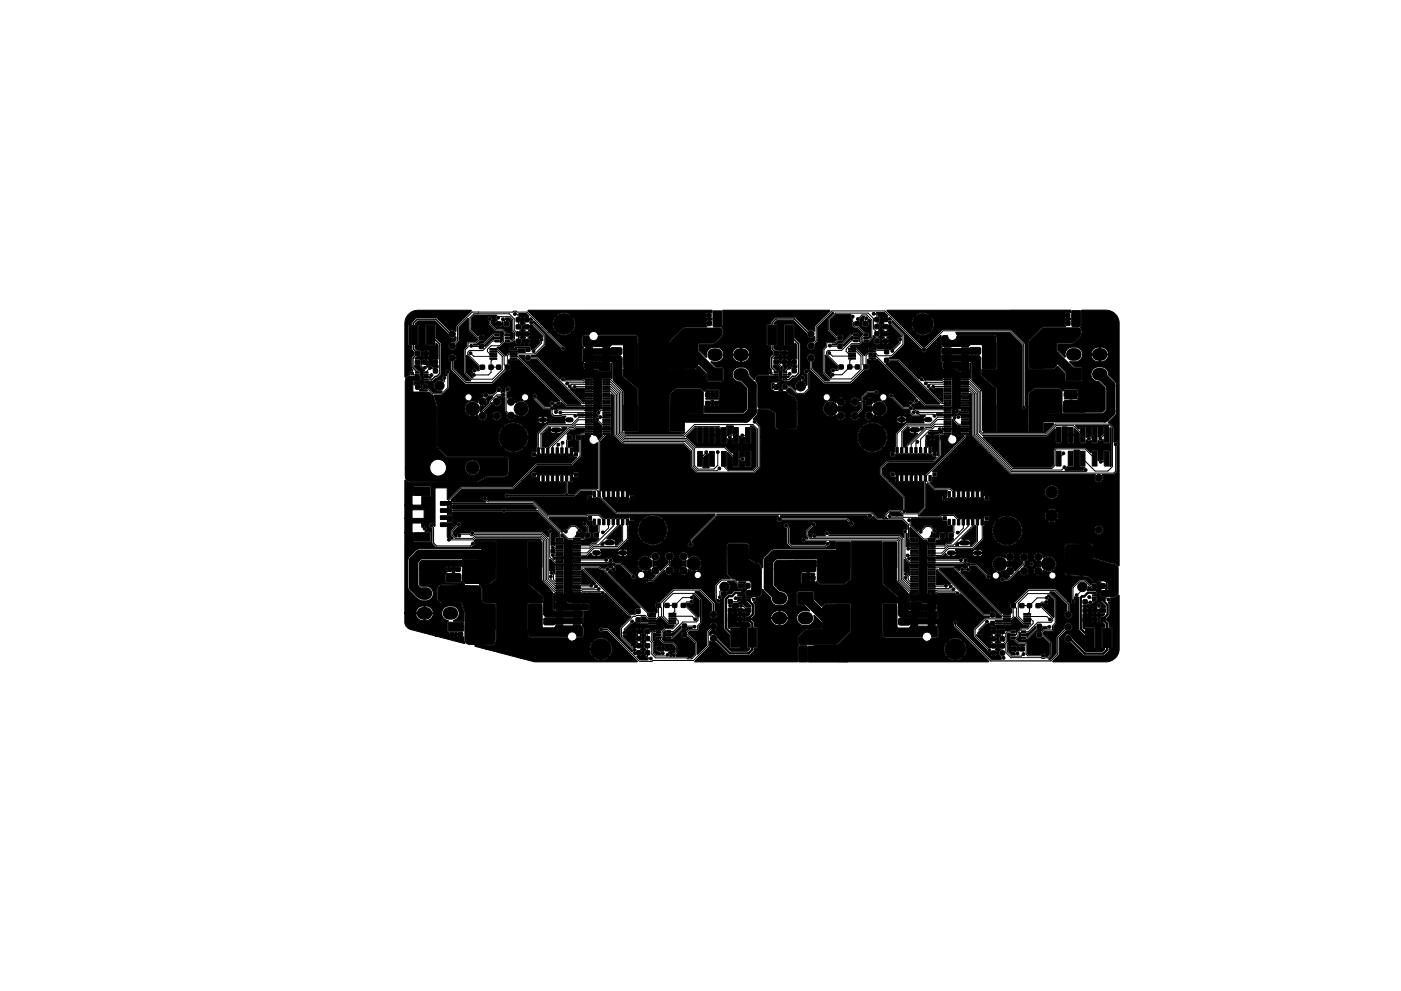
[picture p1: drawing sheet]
<svg xmlns="http://www.w3.org/2000/svg" width="297mm" height="210mm" viewBox="0 0 297 210" stroke-linecap="round" stroke-linejoin="round" font-family="sans-serif">
<g fill="#000" stroke="#000" stroke-width=".21">
<path d="M86.2 80.1l.7-.3 2 .1a.48 .48 0 0 1 .2 .5 .48 .48 0 0 1-.5 .4h-1.1v2.4h3.5l.8 .7 .7 2.1v8.9l2.2 2.1 12.6 .1 .4 .4v2.5a1 1 0 0 1-1 1h-3.5l-2.3 1.2-14-.1a1 1 0 0 1-1-1v-1.8h5.2a1.78 1.78 0 0 0 1.8 1.7 1.78 1.78 0 0 0 1.8-1.8h3.9a1.61 1.61 0 0 0 2.3 1.5 1.61 1.61 0 0 0 .2-2.8 1.61 1.61 0 0 0-2.5 1.1v.2h-3.9a1.78 1.78 0 0 0-1.9-1.8 1.78 1.78 0 0 0-1.7 1.9h-5.2v-18.5zM88.1 76.4h.9v.9h-.9zM88.1 74.6h.9v.8h-.9zM88.1 79.9h.8v.3h-.8zM88.1 79.4h.8v.3h-.8zM88.1 78.9h.8v.3h-.8zM86.7 69h1.9v4.1h-1.9zM89.8 76.4h.9v.9h-.9zM89.8 74.6h1v.8h-1zM90 78.9h.8v.3h-.8zM90 79.4h.8v.3h-.8zM90 79.9h.8v.3h-.8z"/>
<path d="M91.9 78.3h.8v.8h-.8zM91.9 76.4h.8v.9h-.8zM90.4 69h1.8v4.1h-1.8zM98.9 75.4h.2l2.5 2.5-.1 .5h-.5a.5 .5 0 0 0-.9 0v.2l.1 .4-.2 .5 .3 .6-.2 .1-1.2-1.2zM88.6 68.1h3.6l2.8 2.8 .3 .6 .7 .3 .7-.3v.7l-.5 .4a.88 .88 0 0 0-1.1 .8 .88 .88 0 0 0 1.1 .9 .88 .88 0 0 0 .5-1.3l.6-.6v-3l2-1.9 .1 2.6 1.9 1.9-.4 .5-1.8 .1-.1 .9-.6 .7v5.1l1.4 1.5h-.9l-2.6-2.6-.1-1.4a.88 .88 0 0 0 .3-1.4 .88 .88 0 0 0-1.4 .1 .88 .88 0 0 0 .5 1.3v1.7l3 3h5.7l3-2.9h.6l.3-.3v-.7l-.4-.5v-.7h1l.1-.4 .1 .4h.7l.2-.2 8.8 8.8-.7 .3h-.5a.51 .51 0 0 0-.9 0 .54 .54 0 0 0 .3 .7l-.3 .3h-1l-1.8-1.9a.51 .51 0 0 0 0-.6 .51 .51 0 0 0-.5-.3l-.3 .2-.1 .3 .3 .7 2.1 2.2h1.4l.1 .9 .5 .6h1.8l.8-.1 .1 .1-.4 .6 1.2 .1-1.2 .1 .3 .5-.1 .1h-3.8l.2-.6h-1v.6l.7-.1v.2l-2 2v2.8l-.2 .3v.8l-1 .1v.9l.9 .1 .2-.5 .8-.1 .3 .1 .8-.1 .2 .1 .8-.1 .2 .1 .8-.1 .2 .1 .8-.1 .2 .1 .8-.1 .7 .1 .3-.1 .8 .1 .1 .5 .6 .1v.1l-1.2 1.2h-7.4l-5 5h-10.8l-2.9 2.7-.1-.1v-2.4h-2.6v8.1l-.1 .1a.73 .73 0 0 0-.9-.7l-.3 .5 .2 .3 .5 .3v3.2l.8 .8 7.4 .1 .5-.4a.5 .5 0 0 0 .4-.3 .5 .5 0 0 0-.1-.6l-.1-.1 .5-.5h13.4l.3 .3-.1 .1h-2.6l-.2 .2v8.9l3.3 2.9-.1 1.2h-3l-.2 .2v6.5l.4 .6 .4 .1h7.7l.4 .5 .5 .2h4.6l1.6 1.6 1.6-1.6a2.38 2.38 0 0 0-3.2 0h-4.2l.4-.3 .3-.4h1l.4-.4 .1-1.6-.4-.7 .3-.4 .1-2.4 .7-.2 .4-.3 .1-.7-.1-.4-.6-.3h-3.8l-.5-.5h1.4v.4h3.4v-1.8h-1.5l.3-.2h3.6l.5 .5h.3l.5-.4 4.6 4.7 .7 .1-2.3 2.4v2.1l2.5 2.6 .1 .4-5.1-4.9-1.2-.1a.5 .5 0 0 0-.8 .1v.1a.51 .51 0 0 0 .5 .7l.4-.2h.8l6.4 6.5h-21.7l-3.6-.9h16a2.37 2.37 0 0 0 3.2 0l-1.6-1.6-1.6 1.6h-16l-6.7-1.8h21.9l.2 .9 .4 .8 1.6-1.7h.3l1.7 1.7a2.38 2.38 0 0 0 0-3.3l-1.7 1.6h-.3l-1.6-1.6-.4 .7-.2 .9h-21.9l-2.4-.6 .1-.2 3.5 .1 .5-.3 .4-.7v-7.9l-.2-.2h-2.2l-.5-.6-.1-2.4-.6-.8 2.2-.1 1.4-1.1v-7.8l-.1-.3h-3.1l-.2 1.6h-12.8l-.8 .4-1.4 1.3-.3 .6 .1 6.3 1.6 1.8 1.1 .6 1.1 .1 .6-.2 .6-.5 .3-.8a1.54 1.54 0 0 0-1.5-1.6h-1.1l-.4-.4v-3.3h8.1v-.6l-.5 .1-.2 .5h-.4v-.4l-.4-.2h-.2v.6h-.2v-.6l-.4 .1-.1 .5h-5.7v-1.2l.6-.6h8.3v1.3l-.6-.1v.7l-.9 .1 .1 .5h-.5v-.5h-1.3l.2 .6-.4 .5v1.2l.2 .4 .3 .2 2.6-.1 .4-.3 .6 .6h-4.9l-.8 .5-.2 .7v1.9l.6 .7 .6 .2 4 .1 .6 2v1.7h-2.2v-.2l.5-.2 .5-.6a1.55 1.55 0 0 0 0-1.4l-.4-.4-.6-.4h-1.5l-.4 .3-.5 .6-.1 .5v.7a1.54 1.54 0 0 0 1.3 1l.1 .1-.3 .4v1.6l.4 .4v.3h1.4l.1-.4 .2 .1v.3h.8v.7h.7l.2 1.3-6.3-1.6h2.9l.3 .4h.7l.3-.1 .1-.3h.3l.2 .3h.4v-.5h-.6v.2l-.9-.2v.6h-.2v-.6h-.6v.2h-2.9l-5.3-1.4a1.78 1.78 0 0 1-1.2-1.4v-1.9h2.4v.2a1.55 1.55 0 0 0 1.4 1.3h.3a1.58 1.58 0 0 0 1.9-1.5h-1.7v1.5h-.2v-1.5h-4.1v-.2h6.1a1.54 1.54 0 0 0-1.5-1.4h-.3v1.4h-.2v-1.4a1.54 1.54 0 0 0-1.7 1.4h-2.4v-17h1.8l.1 1.8 .1 .2h3.5l.1-.2v-1.9l-1.3-.2a.56 .56 0 0 0 .4-.5 .56 .56 0 0 0-.5-.6l-.6 .2v-.8h-2v2h-1.6v-3h4.1v-1.8h-2.5v1.8h-1.6v-2.8h3.6v-1.8l1.8-.1 .2-.1v-2l-.2-.1-3.5 .1v1.8l-.3 .1v2.1h-1.6l.1-5.3 1 .4 14 .1 .5-.2 1.9-1h3.8l.6-.5 .2-.6v-2.6l-.1-.4-.4-.2-12.6-.1-1.8-1.7h13.7a3.2 3.2 0 0 0 4.3 0l-2.2-2.2-2.1 2.2h-13.7l-.3-.3v-2.1h12.9l.2 1.1 .7 1.2 2.2-2.2h.3l2.2 2.2a3.1 3.1 0 0 0 0-4.4l-2.2 2.2h-.3l-2.2-2.2a3.1 3.1 0 0 0-.9 2.1h-12.9v-2.2h14l2.1 2.1 2.2-2.1a3.2 3.2 0 0 0-4.3 0h-14v-3.8h5.8a1.72 1.72 0 0 0 1 1.5 1.72 1.72 0 0 0 1.8-.2l.1 .1a.96 .96 0 0 0 .9 1.1 .96 .96 0 0 0 1-.9h1.1a.96 .96 0 0 0 .9 .9 .96 .96 0 0 0 1-1l-.3-.7-.7-.2-.6 .2-.3 .7h-1.1l-.2-.5-.4-.5 1.4-1.4 .2-.4 .6 .7a.96 .96 0 0 0 1.4-.8l-.2-.6-.7-.5v-.1l.6-.1 .5 .4h.5v2.8l.5 .6a.99 .99 0 0 0 .6 1.4h5.9l.4 .5 .6 .1v-.6h-6.6l.6-.2h7.2l-.2-.4-.5-.3h-.3v.7h-.2v-.7l-.6 .1-.4 .6h-5l.2-.4 .1-.6 .2 .1a1.69 1.69 0 0 0 2.4-.6 1.69 1.69 0 0 0-.7-2.4l.2-.1a.76 .76 0 0 0 .7-.4 .76 .76 0 0 0-.2-.8l-.5-.3a.76 .76 0 0 0-.8 .6l.1 .6 .3 .3-.1 .1h-.7l-.9 .3-.2-.8-.8 .7 .6-.8a1.09 1.09 0 0 0-1.3 0v-1.3a.61 .61 0 0 0 .7-.6 .61 .61 0 0 0-.6-.6 .61 .61 0 0 0-.6 .7l-.1 .5h-.8a.62 .62 0 0 0-.2-1.1 .62 .62 0 0 0-.8 .7l-.7 .8h-1a.64 .64 0 0 0-.9-.2 .64 .64 0 0 0-.2 .8l-.7 .3 1.4 1.3a.99 .99 0 0 0-.1-1.3l.5-.4 1 .1-.8 .9v.4l-1.9 1.9v-1.3l.7 .1 .4-.2-1.3-1.4-.3 .8-.9-.3h-.7a.97 .97 0 0 0 .3-1.2l-.6-.4a.76 .76 0 0 0-.8 .5 .76 .76 0 0 0 .3 .9l.6 .3-.7 .6-.3 .9h-5.8v-.7l-.7-2.1 1.7-.1 1.4-1.4 .2-3.3a.51 .51 0 0 0-.1-.7 .51 .51 0 0 0-.7 .1 .51 .51 0 0 0 0 .7l.2 .5-.2 .1a.51 .51 0 0 0-.6 0 .51 .51 0 0 0-.1 .6l.2 .2-.2 .2a1.19 1.19 0 0 0-1.3 0l-.5 .6a1.26 1.26 0 0 0 .4 1.3 1.26 1.26 0 0 0 1.3 .3l-.2 .3h-1.7l-.9-1-.2-.8-.8-.2-.4 .4 .1 .8 .3 .2h.6l.1 .2-1.6 .1-.1-.2 .3-.2 .1-.4h-.7l-.1-.2h.8l-.2-.5-.4-.2v.7h-.2v-.7l-.8 .3 .1-.6 1.1-.1 .4-.6-.2-.6v-.9l-.4-.1-.8-.8 .1-.4h.9l1.1 1-.3 .4 .1 1h1.3l.3 .2-.1 .2-1.5-.2 .1 .8h1.7l.8-.7 .4-.1 .8-.8v-6.3l-1.2-1.3v-2.7l-.2-.2h-1.9l-.1 .2v4.2l.1 .1h1.9l.3-.5 .4 .4v2.9l-.5 .1v1.3h.5v.5h-.9l-.4-.2a.52 .52 0 0 0-.9 .1 .23 .23 0 0 1-.3-.3 .23 .23 0 0 1 .4-.1l.2-.3h.7l.2 .3h.3v-.5l-1.2 .2v-.3h-1.5v.4l-.2-.1v-.4h2.9v-.6l-.4 .1-.1 .5h-2.4l1.7-.1v-.2l-.2-.3h-.4v.5h-.2v-.5h-.3l-.3 .2-.1 .3h-.2l-.3-.5-1-.1 .4-.4 .7-.1 .2-.3h.2l.4 .4 .9-.1 .2-.3v-.2h-.6v.5h-.2v-.5h-.6l-.1 .2h-.2v-.4h1.7l-.2-.6h-.4v.6h-.2v-.6l-.4 .1-.3 .5h-.2l-.1-.5-.8-.1-.4-.4v-.5l.6-.1 .2-.2v-4.1l-.2-.2h-.6zM86.7 66.6a2.79 2.79 0 0 1 1.9-.8h11.3v.2l-3.2 3.2v1l-.1 .1a.88 .88 0 0 0-1.1-.2l-.2 .1-2.9-2.8h-4l-1 .9-.1 .5-.7 .1-.1 4.3 .7 .1 .1 .9 .5 .6v.4l-.6 .7v2.2l.3 .4-.2 .1a.5 .5 0 0 0-.4 .7v.3l-1.1 .4 .1-11.7 .2-.9zM99.9 67.5l.7-.7h4.6l.1 .2-.1 .1a.63 .63 0 0 0 .2 .9l-.4 .3v.3h1.4v-.3l.2-.1 .2 1.1 1 .1 .3-.2v-.8l-.2-.3-.5-.1-.3-.5 .9-.1 .4 .5v2.2l.4 .6v1l-.3 .4h-.2l-.1-.3-.7-.1v-.1h.7v-.9l-.7-.1-.9-.8-1.3-.1-.8-.7h.5l.3 .4h.7l.4-.2v-.4h-.6v.6h-.2v-.6h-.6v.2h-.5l-.4-.5 .1-.4a.51 .51 0 0 0 0-.8 .51 .51 0 0 0-.8 .1 .51 .51 0 0 0 .2 .7v.8l1.4 1.3 1.4 .1 .4 .4-.3 .5v1.1l-.4 .4-.1-.9h-1.3v.3l-.5 .1-1.3 1.3h-.2l.1-.3 1.8-1.8h.1v.2h1.3v-.9l-1.1-.1-.6 .3-1.9 1.9-.8 .1-.3 .3h-.8l-.1-.2h.7l.7-.6 .8-.2 .1-.8-.4-.4h-.6l-.4 .2-1.4-1.3zM101.9 77.5h.8v.8h-.8zM101.6 73.1h.9v.8h-.9zM101.6 71.3h.9v.8h-.9zM103.7 77.5h.8v.8h-.8zM105.3 77.5h.9v.8h-.9z"/>
<path d="M103.9 76h1.4v.2h-1.4zM103.9 75.5h1.4v.2h-1.4zM103.9 75h1.4v.2h-1.4zM103.9 74.5h1.4v.2h-1.4zM103.9 74h1.4v.2h-1.4zM104.9 72.1h.9v.4h-.9zM104.9 71.5h.9v.4h-.9zM104.9 70.8h.9v.4h-.9zM105.2 68.3h1v.8h-1zM107.1 77.5h.9v.8h-.9zM106.9 68.3h1v.8h-1zM107.1 70.8h.9v.4h-.9z"/>
<path d="M107.1 71.5h.9v.4h-.9zM107.1 72.1h.9v.4h-.9zM109.5 68.9h.9v.9h-.9zM109.5 72h.9v.8h-.9zM108.2 74h1.4v.2h-1.4zM108.2 74.5h1.4v.2h-1.4zM108.2 75h1.4v.2h-1.4zM108.2 75.5h1.4v.2h-1.4zM108.2 76h1.4v.2h-1.4zM109.5 70.5h.8v.8h-.8zM109.5 67.4h.8v.9h-.8zM111.2 68.9h.9v.9h-.9z"/>
<path d="M111.2 72h.9v.8h-.9zM110.1 75.4h1.2v.9l.3 .3h.8l.3-.4h1.1l9.4 9.5-3 .1-10.2-10.2zM110 66.6l1.7-.1 .5 .6-.4 .1v.5h.6l.1-.3 .4 .5-.1 .1h-1.8l.1 .3 .2 .3-.3 .3-.1 .3h1.5v-.3h.3l2.4 2.4v.2l-.7 .3-.1 .4 .2 .5-1.3 1.3-.5 .2-.1-.6-.3-.2-3.1 .1-.4 .3h-.8v.7h1.8l.1-.5h1.3l.2 .8-3.4-.1-.8 .8-1.8-1.7 .6-.2 .9-.9h1.1l.7-.1 .4-.3 .1 .5 .4 .3h.7l.4-.4h.2l.4 .4h.7l.4-.4v-.2h-.6v.6h-.2v-.6h-.7v.2h-.2v-.4h1.7l-.1-.4-.3-.3 .3-.3 .1-.3h-1.4l.1 .3 .3 .3-.4 .3-.1 .4h-.2l-.1-.5-.4-.2 .4-.5v-.6l-.4-.4 .5-.5h.2l.5 .5-.3 .3-.1 .4h1.4l-.1-.4-.3-.3 .3-.3 .1-.3-1.5-.1v.2h-.2l-.1-.7-.3-.4 .2-.2 .1-.6h1v-.5l-.5 .1-.1 .4h-.4l-.1-.3-.3-.3zM111.5 73.7h.8v.8h-.8zM111.5 75.5h.8v.8h-.8zM111.3 70.5h.8v.8h-.8zM111.3 67.4h.8v.9h-.8zM123.6 75.5l7.8-.1 .5 .5v3.9l3.2 2.8-.1 8.8-2.7-.1v-8.2l-2.3-2.5v-3.5l-.3-.3-.4-.1h-5.6l-.1-.1zM124.1 72.4h1.5v.3h-1.5zM124.1 72.9h1.5v.3h-1.5zM124.1 73.4h1.5v.3h-1.5zM124.1 73.9h1.5v.3h-1.5z"/>
<path d="M124.1 74.4h1.5v.3h-1.5zM124.1 74.9h1.5v.3h-1.5zM124.1 75.4h1.5v.3h-1.5zM124.1 75.9h1.5v.3h-1.5zM124.1 76.4h1.5v.3h-1.5zM124.1 76.9h1.5v.3h-1.5zM124.1 77.4h1.5v.3h-1.5zM124.1 77.9h1.5v.3h-1.5zM124.1 78.4h1.5v.3h-1.5zM124.1 78.9h1.5v.3h-1.5zM124.1 79.4h1.5v.3h-1.5zM124.1 79.9h1.5v.3h-1.5z"/>
<path d="M123.7 71.4l1.1-.2a1.12 1.12 0 0 0 1.6 .9l.6-.9 7.9 .1 .2 .5-.1 6.2-.4 .2h-1.8l-.5-.2-.1-4.9h-2.5l-.7 .4h-5l-.4-.4v-1.4zM122.4 78.5h3.4v.4h3.5v1.3l-6.9 .1zM124 77l.4-.1h4.6l.4 .4v1.1l-.3 .3h-1.9l-.2-.1v-.4h-2.9l-.2-.4zM127.8 72.4h1.5v.3h-1.5zM127.8 72.9h1.5v.3h-1.5zM127.8 73.4h1.5v.3h-1.5zM127.8 73.9h1.5v.3h-1.5zM127.8 74.4h1.5v.3h-1.5zM127.8 74.9h1.5v.3h-1.5zM127.8 75.4h1.5v.3h-1.5zM127.8 75.9h1.5v.3h-1.5zM127.8 76.4h1.5v.3h-1.5z"/>
<path d="M127.8 76.9h1.5v.3h-1.5zM127.8 77.4h1.5v.3h-1.5zM127.8 77.9h1.5v.3h-1.5zM127.8 78.4h1.5v.3h-1.5zM127.8 78.9h1.5v.3h-1.5zM127.8 79.4h1.5v.3h-1.5zM127.8 79.9h1.5v.3h-1.5zM129.6 77.1l.2 .1-.1 3.1-.4-.2v-.2h.2v-.2l-.2-.1 .2-.4-.2-.1v-.2h.2zM123.6 74.1l5.8-.1 .4-.3h1.8l.3 .3v1l-.3 .2h-7.9l-.1-.1zM132.3 72.8h2.9v5.4h-2.9zM142.2 72.8h2.9v5.4h-2.9zM150 69.8h.8v1h-.8z"/>
<path d="M150 68.1h.8v1h-.8zM149.9 66.5h.8v.8h-.8zM151.7 69.8h.8v1h-.8zM151.7 68.1h.8v1h-.8zM142.5 72.1l2.3-2.2 .5-.3h7.2l.4 .2 .2 .4-.1 .9-1.5 1.6-.5 .1h-3v4.4a1 1 0 0 1-1 1h-3.8a1 1 0 0 1-1-1v-4.4zM151.7 66.5h.9v.8h-.9zM151.2 66h1.9v3l-.2 .4-1.6-.1-.1-.3zM160.4 80l.6-.3 3.9 .1 .2 .4-.2 .7-1.4 .2v1.5l.8 .5 2.6 .1a1.56 1.56 0 0 0 1.3 1l.7 1.1v5.4l-.5 .2-3.7-.1-.2-.4v-2.8l-1.4-.9h-1.9l-.5-.3v-4.6l-.5-1 .1-.5zM164.1 76.4h1v.8h-1zM164.1 74.5h1v.8h-1zM164.1 79.9l.8-.1v.3h-.8zM164.1 79.4l.8-.1v.3h-.8z"/>
<path d="M164.1 78.9l.8-.1v.3h-.8zM162.8 69h1.8v4.1h-1.8zM165.9 76.4h.9v.8h-.9zM165.9 74.5h.9v.8h-.9zM166 78.9l.8-.1v.3h-.8zM166 79.4l.8-.1v.3h-.8zM166 79.9l.8-.1v.3h-.8zM168 78.2h.8v.9h-.8zM168 76.4h.8v.8h-.8zM166.4 69h1.9v4.1h-1.9zM175 75.4h.1l2.5 2.5-.1 .4h-.5a.5 .5 0 0 0-.8 0v.8a.5 .5 0 0 0 0 .8l.1 .2h-.2l-1.1-1.1zM112 65.8h38.9v.5h-.5v1.3l.5-.1 .1 .3-.5 .1-.1 .8h-.7l.1 .7-4.8 .1-2.8 2.6-.2 .7v5.5l.1 .1h4.9l.7-.2 .5-.5 1.5 1.6 .1 1.3 .2 .4h3.1l.4-.4-.1-2.5-.3-.2h-1.4l-1-1.1h1.5l.4-.2 .6-.5 .3-.7h1.8a1.56 1.56 0 0 0 1.7 1.4h.2a1.52 1.52 0 0 0 1.8-1.5l-1.8 .1v1.4h-.2v-1.5l-3.5 .1v-.3h5.4a1.51 1.51 0 0 0-1.4-1.4h-.3v1.4h-.2v-1.4a1.56 1.56 0 0 0-1.7 1.4h-1.8l-.1-.2a1.57 1.57 0 0 0-1.4-1.2l-1.2 .1-.6 .4-.4 .6-.1 1-1.5-1.4 .1-1.4h3.1l1.7-1.6 .2-.7v-.7l-.3-.4 .3-.6v-3.2h22.6v.2l-3.1 3.1v1.1l-.2 .1a.88 .88 0 0 0-1.1-.2h-.1l-2.8-2.7h-4.3l-.9 .9-.1 .4-.6 .1-.1 .2v4.2l.7 .1 .1 .8 .5 .6v.5l-.6 .7v2.1l.3 .5-.6 .3-.1 .7-2.1 .1-.6 .4-.2 .5-1-.9-.1-.7a1.55 1.55 0 0 0-1.3-1l-1.3 .1-.6 .4-.4 .8 .1 .8a1.55 1.55 0 0 0 1.3 1h.3l1.3 1.3v4.6l-.7 .6h-8.2v-1.4l1.1 .1 .3-.3h.4l.3 .3 .7 .1 .3-.3 .1-.3h-.6v.5h-.2v-.5h-.5l-.1 .2h-.4v-.2h-.6v.5h-.2v-.7h.8v-.6h.5l-.1 .6h1.4l-.2-.6 .2-.3v-1.7l-.1-.2-2.8-.1-.4 .4-.9-.7h-5l-1.5 1.3v7.7l.2 .3h3l.1 .2-.3 .3h-12.1l-.3-.5h2.7l.2-.2-.1-8.9-3.2-2.8 .1-1.3h3l.1-.1v-6.7l-.3-.4-.4-.2-7.7 .1-.4-.5a.99 .99 0 0 0-1.6 .4l-1.1 .1-.4 .5v1.6l.3 .5-.3 .4v1.4v1.2l.4 .3-.1 .9 .2 .5 2.8 .1 .5 .4h-1.4v-.4h-3.4v1.8h1.4l-.2 .2h-3.8a.51 .51 0 0 0-.4-.5 .51 .51 0 0 0-.5 .4h-.2l-4.7-4.7-1.4-.1 .1-.2 .9-.1 2.1-2.2-.1-2.1-2.5-2.5v-.4l5.8 5.7 .2 .5a.5 .5 0 0 0 .8-.2 .53 .53 0 0 0-.6-.7l-2.9-2.9h1.5a2.37 2.37 0 0 0 3.3 0l-1.7-1.6-1.6 1.6h-1.5l-1.7-1.8h2.4l.2 .9 .5 .8 1.6-1.7h.3l1.6 1.7 .5-.8 .1-1.1h28.4v-.7l-.5 .2-.1 .5h-27.8l-.5-1.3h28.2l.2 .4h.4v-.5l-.6-.1v.2h-28.2l-.1-.1-1.6 1.6h-.3l-1.6-1.6-.5 .7-.2 .9h-2.4l-1.8-1.7h5l1.6 1.6 1.7-1.6-.2-.2h29.2v-.5l-.4 .1-.2 .4h-28.6l-.2-.1a2.38 2.38 0 0 0-2.9 .3h-5l-.9-1z"/>
<path d="M117.3 86l.2-.2 .6 .2a.5 .5 0 0 0 .8-.2l.1-.5 1.1 1 5.7 .1v-6.1h1.8v6.1h1.9v-2.8l.6 .5 .1 8.4 1.8 1.8h12.9l1.5 1.5v3.4l1.3 1.3 12.3-.1 1.2-1.2v-4.1h21.6a3.2 3.2 0 0 0 4.3 0l-2.2-2.2-2.1 2.2h-21.6v-2.4h20.5a3.1 3.1 0 0 0 .9 2.3l2.2-2.2h.3l2.2 2.2a3.2 3.2 0 0 0 0-4.4l-2.2 2.2h-.3l-2.2-2.2a3 3 0 0 0-.9 2.1h-20.5v-2.4l-.7-.8a.58 .58 0 0 0-.8-.5l.9-1.1 .1-1.1 2.3 .1 1.3 .9v2.7l.2 .4 .3 .2h3.8l.4-.2 .1-.4h13.7l2.1 2.1 2.2-2.1a3.2 3.2 0 0 0-4.3 0h-13.7v-3.8h5.4a1.72 1.72 0 0 0 1 1.5 1.72 1.72 0 0 0 1.8-.2v.1a.96 .96 0 0 0 .9 1.1 .96 .96 0 0 0 1-1h1.1a.97 .97 0 0 0 1 1 .97 .97 0 0 0 .9-1l1.1 .1a.97 .97 0 0 0 1 .9l5.8-.1 .3 .6 .7 .1v-.7h-6.5l.4-.2h7.3l-.2-.4-.5-.2h-.3v.6h-.2v-.6h-.3l-.5 .2-.2 .4h-5.1l.4-.9a1.67 1.67 0 0 0 2.4-.4 1.67 1.67 0 0 0-.7-2.4l.1-.2a.77 .77 0 0 0 .8-.7l-.2-.5-.6-.3a.76 .76 0 0 0-.6 .5 .76 .76 0 0 0 .1 .8l.2 .3h-1l-.6 .4-.3-.9-1.3 1.4a.98 .98 0 0 0 1.1 .1v1.3l-.5-.1-.5 .1-.3 .3-.2 .5h-1.1v-.5l.7-.8v-1.7h.4l.2 .6 .6-.6-.6-.6-.2 .6h-.4l.1-.7h.7l.6 .6 .6-.6a.9 .9 0 0 0-1.2 0h-.7l1-1h1.4l.1 .1a.52 .52 0 0 0 .8-.1 .52 .52 0 0 0-.2-.8 .52 .52 0 0 0-.7 .3h-1.7l-1.3 1.3v.8l-.4-.6-.5-.2h-.6l-.4 .4a.97 .97 0 0 0 .4 1.4 .97 .97 0 0 0 1.4-.7l.1 .1v1.2l-.7 .7-.4-.1-.5 .1-.3 .3-.2 .5h-1.1l-.1-.5-.3-.3-.5-.1-.6 .1v-1.3l.7 .1 .5-.2-.8-.8h.3l.6 .6a.95 .95 0 0 0 .1-1.1l-.7 .5h-.3l-.6-.6-.2 .8-.7-.3-1-.1 .4-.5h1.7l.6 .6 .6-.6a.9 .9 0 0 0-1.2 0h-1.7l-.1-.6-.5-.4a.76 .76 0 0 0-.8 .5 .76 .76 0 0 0 .2 .9l.7 .3-.7 .6-.3 .9h-5.4v-1.6l-.4-.8-.4-.3a1.3 1.3 0 0 1-1.2-.8l-.4-.4 .4-.4 .3-.1 1.4 1.4 1.8-.1 1.1-1.1-.1-3.5a.77 .77 0 0 0-.7-.7 .5 .5 0 0 0-.5 .5 .5 .5 0 0 0 .4 .5l.3 .1v2.4l-.7-.9v-.4l.3-.4a.5 .5 0 0 0-.7-.5 .5 .5 0 0 0-.2 .8v.3l-.7 .3-.4 .5-.1 .4 .1 .9-.9-.9-.7-.1-.4-.4h-.6l-.3 .2-.1 .8 .2 .5h-.7v-.7h-1.3v.3l-.2-.1 .1-1.1h.3l-.2 .7h1.3v-.4l-.4-.3 .4-.3 .1-.4-.2-1.8-.4-.2-.7-.7v-.5l1 .1 .3 .2v.6l.6 .3-.1 1.3 1.6-.1-.3 .4-1.3-.1 .1 .7 1.5 .1 .7-.7 .8-.1 .8-.9v-6.2l-1.2-1.4v-2.7l-.2-.1h-1.9l-.2 .2v4.2l.2 .1h1.9l.3-.5 .4 .4v2.9h-.5v1.4h.4l.1 .4-.9 .1-.2-.2a.58 .58 0 0 0-1-.1l-.1 .5-.4 .4h-.3l.1-.5-.2-.6 .8-.1 .3-.3h.6l.2 .4h.4v-.6l-1.2 .2v-.2h-.7v.6h-.2v-.6h-.6l-.1 .2-.2-.4h3v-.6l-.5 .2-.1 .4h-2.4h1.7l.1-.2-.3-.3-.4-.1v.6h-.2v-.6h-.3l-.3 .3v.3h-.3l-.2-.5-1.1-.1 .5-.5h.6l.3-.4h.2l.4 .4h.8l.3-.4v-.2h-.7v.6h-.2v-.6h-.6v.2h-.2v-.4h1.7l-.3-.5h-.4v.5h-.2v-.5h-.4l-.2 .5h-.2l-.2-.4-.8-.2-.4-.4 .1-.5h.6l.1-.2v-4.1l-.1-.2h-.6v-.2l.6-.6h3.6l2.8 2.8v.2a.87 .87 0 0 0 .7 .7 .87 .87 0 0 0 .8-.3l.2 .7-.5 .5a.88 .88 0 0 0-1.2 .8 .88 .88 0 0 0 1.1 .9 .88 .88 0 0 0 .6-1.3l.6-.7v-2.9l3.1-3.1h.2v.1l-1.3 1.4v2.1l2 2.1-.5 .4-1.8 .1-.1 1-.6 .7v5l1.4 1.6h-.9l-2.6-2.7v-1.4a.88 .88 0 0 0 .2-1.4 .88 .88 0 0 0-1.3 .2 .88 .88 0 0 0 .4 1.3l.1 1.7 3 2.9h5.7l3-2.8 .5-.1 .4-.2v-.8l-.4-.4v-.8l1 .1 .1-.4 .1 .4h.6l.3-.2 8.2 8.2-.4 .5a.23 .23 0 0 1 0 .3 .23 .23 0 0 1-.4-.1 .51 .51 0 0 0-.7 .1 .51 .51 0 0 0 .1 .7l.1 .2-.3 .2h-1l-2.2-2.3a.51 .51 0 0 0-.4-.6 .51 .51 0 0 0-.6 .5l.2 .4 .5 .2 2.3 2.3 1.3 .1 .1 .1 .1 .7 .5 .6h1.4l.3-.2h1l.1 .2-.4 .3-.1 .3 1.2 .1-1.2 .1 .2 .5-.1 .1h-3.7l.2-.6h-1v.7l.6-.1 .1 .2-2.1 2v2.8l-.2 .2v.8l-1 .2v1h1l.2-.5 .8-.2 .2 .2 .8-.2 .2 .2 .8-.2 .2 .2 .8-.2 .2 .2 .8-.2 .2 .2 .8-.2 .8 .2 .2-.2 .8 .2 .1 .5h.8l.1 .1-.7 .7h-9.6l-1.6 1.5v1.6l4.9 4.9v2.3l-.3 .3-2.7-.1-.8 .8-.1 .6-.2 .2h-1.3l-1.3-1.2-54.1-.1-2.8-2.9 .6-.1 .8 .1 .2-.1 .8 .1 .2-.1 .8 .1 .2-.1 .8 .1 .2-.1 .9 .1 .1 .6h.8l.2-.2v-.7l-.1-.2-1.3-.2v.7h-.2v-.9h.6v-.5l-.4-.2v.7h-.2v-.7l-.4 .2-.4-.2v1.6h-.2v-1.6l-.4 .2-.4-.2v1.6h-.2v-1.6l-.4 .2-.4-.2v1.6h-.2v-1.6l-.4 .2-.4-.2v1.6h-.2v-1.6l-.4 .2-.4-.2v1.6h-.2v-1.6l-.4 .2-.2-.2v-10.3l1.2-1.3 .9-.1 .1-1.1h-1.9v1l.1 .3-.8 .8-.4-.7-.7-.3v-1.2l-1.9 .1-.1 .6h-.6l-.3 .3-.8 .1-.2 .3 .1 .9 .7 .2v2.3h-1.1l-.1-1-.6-.1-.3 .1-.2-.2v-1.2l.9-.1 .1-.9-.2-.3h-.9l-.1-.2 .7-.6 .8-.1 .5-.5 3.6 .1v-2h.3l.1 .4 .5 .1 .9 .9v.6h1.9v-2.7l-1-.2 1-.1v-1.2l-1.9-.1-.8 .5a.5 .5 0 0 0-.4 .5 .5 .5 0 0 0 .4 .5l-.1 .3-.4 .1-.2 .4h-.3v-.8l-3.3 .2v-.5l3.3 .1v-1.3l-7.4 .1-.8 .3-.1-.5zM177.9 77.4h.9v.9h-.9zM177.7 73h.8v.9h-.8zM177.7 71.2h.8v.9h-.8zM179.7 77.4h.9v.9h-.9zM177.2 66.7h3.2l-.1 .5 .2 .4 .2 1.6 .4 .5h.7l1.2 1.2-.7 .7v.9l-.2-.1v-.6h-1.3l-.1 .2-.4 .1-1.4 1.3h-.1v-.3l1.8-1.8h.2v.3l1.3-.1-.1-.8-1-.1-.6 .2-2 1.9-.7 .1-.4 .4h-.9v-.2h.7l.7-.6 .7-.1 .3-.3-.1-.9-.9-.1-.4 .2-1.4-1.4v-1.8zM181.4 77.4h.8v.9h-.8zM179.9 75.9h1.5v.3h-1.5zM179.9 75.4h1.5v.3h-1.5zM179.9 74.9h1.5v.3h-1.5zM179.9 74.4h1.5v.3h-1.5zM179.9 73.9h1.5v.3h-1.5z"/>
<path d="M181 72.1h.9v.4h-.9zM181 71.5h.9v.4h-.9zM181 70.8h.9v.4h-.9zM181.3 68.3h.9v.8h-.9zM183.2 77.4h.8v.9h-.8zM182.8 67.1h.5l-.2 .9-.4 .4v.6l.3 .3h.8l.3-.1 .1-.8-.2-.4 .2-.3 .4 .3v3.5l-.3 .3-.8-.1 .8-.2-.1-.8-.7-.1-1.2-1.2 .2-.6-.9-.1 .1-.1h.8l-.2-.5 .1-.5zM183 68.3h.9v.8h-.9zM183.2 70.8h.9v.4h-.9zM183.2 71.5h.9v.4h-.9zM183.2 72.1h.9v.4h-.9zM185.5 68.9h1v.8h-1zM185.5 71.9h1v.9h-1z"/>
<path d="M184.2 73.9h1.5v.3h-1.5zM184.2 74.4h1.5v.3h-1.5zM184.2 74.9h1.5v.3h-1.5zM184.2 75.4h1.5v.3h-1.5zM184.2 75.9h1.5v.3h-1.5zM185.5 67.4h.8v.8h-.8zM185.5 70.4h.8v.8h-.8zM187.2 68.9h1v.8h-1zM187.2 71.9h1v.9h-1zM185.8 66.3h1.7l.7 .7-.3 .1v.6h.5l.1-.3 .5 .4-.1 .1h-1.8v.3l.3 .3-.4 .4v.3h1.4l.1-.3h.3l2.3 2.3v.2l-.7 .3v.4l.2 .6-1.3 1.3-.6 .2-.4-.3-2.2 .2-.4-.4h-1.6l-.1 .8h1v.1l-1 .1-.8 .7-1.7-1.7h-1.1l-.1-.2 .4-.3h1.6l.6-.6 .3 .1h1l.8-.8 .2-.7 .5 .4-.4 .4v.7l.2 .3h.9l.3-.4h.3l.3 .4h.8l.3-.3v-.2h-.6v.5h-.2v-.5h-.6v.1h-.3v-.4h1.8l-.1-.3-.4-.3 .4-.3v-.4h-1.3v.4l.4 .3-.4 .2-.1 .4h-.3l-.1-.4-.4-.2 .4-.5v-.6l-.3-.4 .4-.5h.3l.4 .5-.3 .3v.3h1.3v-.3l-.3-.3 .3-.3 .1-.4h-1.5v.2h-.3v-.7l-.4-.4 .3-.3v-.5h1.1v-.6l-.5 .1-.1 .5h-.5v-.3l-.4-.3zM187.6 74.2h.8v.8h-.8zM187.6 76h.8v.9h-.8z"/>
<path d="M187.3 67.4h.9v.8h-.9zM187.3 70.4h.9v.8h-.9zM189.1 68.1l6.3 6 .1 .4a.5 .5 0 0 0 .7 .1l.2-.5 3.1-2.9-.1 1.8 .4 .7-.3 .4v2.4l.3 .4-.1 .8 .3 .7h2.7l.5 .5h-1.4v-.4h-3.4v1.8h1.5l-.3 .2-3.7-.1a.5 .5 0 0 0-.4-.4 .5 .5 0 0 0-.6 .3l-.2 .1-4-4.1-2-.2-.1-.3 .6-.1 2.5-2.6v-2.1l-2.5-2.5zM187.8 77.2l.6-.1 .3-.4h1.7l8.8 9h-2.9zM199.6 75.4h7.9l.4 .5v3.9l3.3 2.7-.1 8.8h-2.8v-8.1l-.2-.5-2.1-2.1v-3.5l-.2-.3-.4-.1h-5.6l-.1-.2zM200.2 72.4h1.5v.3h-1.5zM200.2 72.9h1.5v.3h-1.5zM200.2 73.4h1.5v.3h-1.5zM200.2 73.9h1.5v.3h-1.5zM200.2 74.4h1.5v.3h-1.5zM200.2 74.9h1.5v.3h-1.5zM200.2 75.4h1.5v.3h-1.5z"/>
<path d="M200.2 75.9h1.5v.3h-1.5zM200.2 76.4h1.5v.3h-1.5zM200.2 76.9h1.5v.3h-1.5zM200.2 77.4h1.5v.3h-1.5zM200.2 77.9h1.5v.3h-1.5zM200.2 78.4h1.5v.3h-1.5zM200.2 78.9h1.5v.3h-1.5zM200.2 79.4h1.5v.3h-1.5zM200.2 79.9h1.5v.3h-1.5zM199.8 71.3l1-.1a1.12 1.12 0 0 0 1.7 .9l.5-.9 7.9 .1 .3 .4-.1 6.2-.4 .3h-1.9l-.4-.3-.1-4.8h-2.5l-.7 .4h-5.1l-.4-.5v-1.3zM198.4 78.5h3.4v.4h3.6v1.3l-7 .1zM200.1 77l.3-.1h4.6l.4 .3v1.1l-.3 .4h-1.8l-.2-.1-.1-.4-2.8-.1-.3-.4z"/>
<path d="M203.9 72.4h1.5v.3h-1.5zM203.9 72.9h1.5v.3h-1.5zM203.9 73.4h1.5v.3h-1.5zM203.9 73.9h1.5v.3h-1.5zM203.9 74.4h1.5v.3h-1.5zM203.9 74.9h1.5v.3h-1.5zM203.9 75.4h1.5v.3h-1.5zM203.9 75.9h1.5v.3h-1.5zM203.9 76.4h1.5v.3h-1.5zM203.9 76.9h1.5v.3h-1.5zM203.9 77.4h1.5v.3h-1.5zM203.9 77.9h1.5v.3h-1.5z"/>
<path d="M203.9 78.4h1.5v.3h-1.5zM203.9 78.9h1.5v.3h-1.5zM203.9 79.4h1.5v.3h-1.5zM203.9 79.9h1.5v.3h-1.5zM205.6 77l.2 .2v3.1l-.4-.2v-.2h.2v-.3h-.2l.2-.5h-.2v-.2h.2zM199.7 74h5.7l.4-.3h1.8l.3 .2v1l-.2 .3h-7.9l-.1-.2zM208.3 72.8h2.9v5.4h-2.9zM218.2 72.8h2.9v5.4h-2.9zM226 69.8h.8v.9h-.8zM226 68.1h.8v.9h-.8zM225.9 66.5h.9v.8h-.9zM227.7 69.8h.8v.9h-.8z"/>
<path d="M227.7 68.1h.8v.9h-.8zM218.5 72.1l2.3-2.3 .5-.2h7.3l.4 .1 .2 .4-.1 1-1.5 1.5-.6 .2h-2.9v4.3a1 1 0 0 1-1 1.1h-3.9a1 1 0 0 1-1-1.1v-4.3zM227.8 66.5h.8v.8h-.8zM227.2 66h1.9v3l-.2 .3h-1.6l-.1-.3zM188 65.9l38.9-.1 .1 .5-.5-.1v1.4l.5-.1v.3h-.5v.8h-.8l.2 .7-4.8 .1-2.9 2.7-.2 .6v5.5l.2 .2h4.9l.6-.2 .5-.5 1.6 1.5v1.4l.3 .3 3.1 .1 .3-.4v-2.5l-.3-.2-1.4-.1-1-1.1h1.4l.5-.1 .5-.5 .3-.8h1.8v.2a1.55 1.55 0 0 0 1.5 1.3l.3-.1a1.58 1.58 0 0 0 1.9-1.4h-1.7v1.4h-.2v-1.4h-3.6v-.2h5.5a1.51 1.51 0 0 0-1.4-1.4h-.3v1.4h-.2v-1.4a1.56 1.56 0 0 0-1.8 1.4h-1.8v-.2a1.57 1.57 0 0 0-1.4-1.2h-1.2l-.6 .4-.4 .7-.1 1-1.5-1.5v-1.3l3.2-.1 1.7-1.6 .2-.6v-.7l-.3-.5 .2-.5 .1-3.2 5.8 .1a2.79 2.79 0 0 1 2.1 2.4v51.8l-.9-.6-1-.1-3.6-1.1v-2.4l-.4-.5-5-.1-.5 .2-.2 .5v5.4l.2 .5 .5 .2 4.3 .3 1 .9 1.7 .2-.3 .7h1.4v-.4l.2 .1v1.2l-.4-.1 .2-.6h-1.4l.1 .4 .3 .3-.4 1 .2 .5v.9l1.1 1v.3l-1 .1 .1-.3a.5 .5 0 0 0-.4-.7 .5 .5 0 0 0-.6 .3l.1 .6-.4 .1v.5h.6l.2-.2 .2 .9 1 .2-.3 .4-.6 .1-.2 .3 .1 .9 .7 .1 .4 .5v.4l-.6 .1-.1 .2v4.1l.1 .2h.5v.1l-.5 .5h-3.5l-2.8-2.8-.3-.5-.4-.2a.47 .47 0 0 0-.8 .1v.1a.93 .93 0 0 0-.1 1.2 .93 .93 0 0 0 1.2 .2l2.9 2.8h4.1l1.1-.9 .1-.6 .6-.1v-4.3l-.6-.1v-.9l-.6-.7 .7-1v-2.2l-.3-.4 .1-.2a.53 .53 0 0 0 .3-.8l1-.1 .9-.5-.1 12.1a2.78 2.78 0 0 1-2.7 2h-11.3v-.1l1.4-1.4v-3.6l1.6-1.5a.88 .88 0 0 0 1.1-.9 .88 .88 0 0 0-1.1-.8 .88 .88 0 0 0-.5 1.2l-1.7 1.8-.1 3.5-1.2 1.3h-.3l.6-.9v-2.7l-1.9-1.9 .4-.5 1.8-.1 .1-.9 .6-.7v-5.1l-1.4-1.5h.9l2.6 2.6v1.4a.88 .88 0 0 0-.2 1.4 .88 .88 0 0 0 1.4-.1 .88 .88 0 0 0-.5-1.3v-1.5l-.4-.6h.6l.1 .3a.51 .51 0 0 0 .7 .1l.2-.4-.2-.4v-.4h.9v6.7l1.2 1.5v2.6l.2 .1h2l.1-.2v-4.2l-.2-.1h-1.9l-.3 .3-.2-.2v-1.5h1.8l.2 .3 .9 .1 .3-.2v-.4h-.6v.6h-.2v-.6h-.6v.2h-1.8v-.4h3.2v-.2l-.2-.3-.4-.1v.6h-.2v-.6h-.3l-.3 .3v.3h-1.8v-1l.9-.1 .2-.4h.7l.3 .4h.8l.3-.2 .1-.3-.7-.1v.6h-.2v-.6l-1.3 .2v-.2h-.5v.6h-.2v-.8h2v-.5l-.5 .1-.1 .4h-1.4h.7v-.3l-.5-.3v.6h-.2v-.6h-.4v-.3l.8-.1 .3-.2 .6 .1 .8-.6 .5-.2v-1.1l-.7-.1 .7-.1v-.6l-.5-.3-1.6-.1 .3-.7 .5 .2 .4 .4 .8-.1 .2-.3v-.7l-.2-.3h-.8l-.4 .4-1.2-1.1-1.3 .1-1.6 1.5v2.5l-.2 .4h-.6l-2.7-2.6h-5.7l-2.9 2.9-.8 .1-.2 .9 .5 .5v.7h-1l-.1 .4-.1-.4h-.7l-.3 .1-7.2-7.1h6.8l.1 .4 .4 .1 .4-.3h1.1l2.1-2.1 .4 .8a.95 .95 0 0 0 1.1 .1l1.9-.1a.93 .93 0 0 0 1.2 0l-.6-.6-.6 .6h-1.8l.4-.7h1.1l.2 .6 .6-.6-.6-.6-.2 .6h-1.1l-.3-.7-.7-.4 .3-.5h.8a.5 .5 0 0 0 .7 .5 .5 .5 0 0 0 .1-.8 .5 .5 0 0 0-.8 .2v.1h-.8v-.5l.5-.4 .2-.5h1.1a.96 .96 0 0 0 1.4 .8l.1 .1v1.2l-.7-.1-.5 .2 1.4 1.4 .2-.8 .7 .3 1 .1a.79 .79 0 0 0-.4 .8 .79 .79 0 0 0 .6 .7 .77 .77 0 0 0 .9-.8l-.2-.5-.7-.3v-.1a1.69 1.69 0 0 0 .7-2.5 1.69 1.69 0 0 0-2.6-.3v-.5a.95 .95 0 0 0-1-.7l-.6 .3-.3 .7h-1.1l-.3-.7-.5-.3-.5 .1-.5 .3a.98 .98 0 0 0 .6 1.5v.4l-1.6 1.6h-.2l-.2-.5-1.4 1.3 .6 .3-.4 .5h-.8a.5 .5 0 0 0-.8 0l-.1 .3h-6.8l-1.5-1.6 .7-.3 .6 .1a.5 .5 0 0 0 .8-.2v-.4a.27 .27 0 0 1-.3-.3 .27 .27 0 0 1 .3-.3l1 .1 2.2 2.3a.5 .5 0 0 0 .6 .5 .52 .52 0 0 0 .4-.6 .52 .52 0 0 0-.6-.4l-2.2-2.2h3.1a1.92 1.92 0 0 0 1 1.6l-.1 .1a.77 .77 0 0 0-.8 .8 .77 .77 0 0 0 1.1 .6 .76 .76 0 0 0 .2-1.2l-.2-.2 .1-.1h.6l.9-.4 .3 .9 1.3-1.4a.98 .98 0 0 0-1.1-.1v-1.3a.98 .98 0 0 0 1.5-.8v-.3a.95 .95 0 0 0-1-.7l-.4 .1a.95 .95 0 0 0-.5 1l-.1 .1a1.67 1.67 0 0 0-1.8-.2 1.67 1.67 0 0 0-1 1.5h-3.1l-.3-.2h-1.1l-.7-.3a.54 .54 0 0 0-.1-.7 .54 .54 0 0 0-.7 .1 .7 .7 0 0 0-.9-.1l-.1 .1h-4.7l-.1-.2h-1.9v1.3h7.6l.7-.3a.86 .86 0 0 0 .3 .9l-.3 .3-.5-.1a.51 .51 0 0 0-.5-.2 .51 .51 0 0 0-.4 .3l-.1 .5-1.1-1-5.7-.2v6.2h-1.8v-6.2h-1.9v2.1l-.3-.1a.56 .56 0 0 0-.6-.6l-.3-.1 .1-2.5 1.1 1h1.9v-1.3h-1.9l-.1 .4-.4-.3 .4-.3h2v-2.8h-1.9l-.1 .6-.7-.1v-2.7l.1-.1 .2 1 .5 .5v.6h1.9l-.1-1.1-1.8-.2v-1.9l.2-.1 2.5 2.6 .9 .1 .1 .6h1.9l.1-.6h.5l.4-.3 .8-.1 .2-.3v-.6l-.4-.4a.74 .74 0 0 0-1 .4v.6l-.2 .2-1.7-.1 .3-1.1 .3 .1a.52 .52 0 0 0 .8-.3 .52 .52 0 0 0-.7-.6l-.6-.6h-1l-.9 .8-.4 .1-.4 .3-1.4-1.3v-1.3l6.1-.1 .4-.2 .1 .7 1 .1 .1 .9 .6 .1 .3-.1 .2 .1v1.3l-.9 .1-.1 .9 .2 .3h.9l.1 .2-.7 .6-.8 .1-.6 .5-3.5-.2v2.8l3.2-.1 .7-.7 .3 .4 .4 .3 1.2-.1 .4-.6h3.4l.5 .6 1.1 .1 .4-.3 .2-.4h-1v.7h-.2v-.7h-5.4v.7h-.2v-.8l1.2-.1-.3-.5 .1-.1h3.7l.1 .1-.2 .5h2.1l-.1-.4-.3-.2h-.5v.6h-.2v-.6h-.7l1.5-1.7h3.4a3.2 3.2 0 0 0 4.3 0l-2.2-2.2-2.1 2.2h-3.4l.5-.6v-1.8h1.8l.2 1.1 .7 1.2 2.2-2.2h.3l2.2 2.2a3 3 0 0 0 .8-2.1v-.3h15.3l.1 .4a.96 .96 0 0 0 1.5 .3 .96 .96 0 0 0-.3-1.6 .96 .96 0 0 0-1.3 .9h-15.3l-.1-.9-.6-1h6a1.45 1.45 0 0 0 1.9 0l-.9-.9-1 .9h-6l-.1-.1-2.2 2.2h-.3l-2.2-2.2a3 3 0 0 0-.9 2.1h-1.8l.2-1.9 .9-.1 .1-.2h1.7l2.1 2.1 2.2-2.1a3.2 3.2 0 0 0-4.3 0h-1.7v-.7l-.1-.2h-.8l-.2 .6-.8 .1-.3-.1-.8 .1-.2-.1-.8 .1-.2-.1-.8 .1-.7-.1-.3 .1-.5-.1-.6-.6h18.9l.4 1 .9-1h.3l1 1a1.46 1.46 0 0 0 0-2l-1 1h-.3l-.9-1-.4 1h-18.9l-.4-.3h-2.5l-.6 .4-4.4-.1 1.2-1.1h26.1l1 1 .9-1a1.43 1.43 0 0 0-1.9 0h-26.1l.6-.7v-5l1.5 1.4h2.8v1.1l-1 .2-.1 .8 .2 .1h.8l.2-.5 .9-.1 .2 .1 .8-.1 .7 .1 .3-.1 .2 .1 .8-.1 .2 .1 .8-.1 .2 .1 .8-.1 .7 .1 .3-.1 .8 .1 .2 .5h.8l.1-.1-.1-1-1.3-.1v.7h-.2v-.9h.6v-.4h12.8a1.48 1.48 0 0 0 2.1 1.4 1.48 1.48 0 0 0 .3-2.6 1.48 1.48 0 0 0-2.4 1v.2h-12.8l-.1-.3h-.2l-.1 .7h-.2v-.7l-.4 .1-.3-.1-.1 1.6h-.2v-1.6l-.4 .1-.3-.1-.1 1.6h-.2v-1.6l-.4 .1-.3-.1-.1 1.6h-.2v-1.6l-.4 .1-.3-.1-.1 1.6h-.2v-1.6l-.4 .1-.3-.1-.1 1.6h-.2v-1.6l-.4 .1-.5-.1-.7-.6h-3.3l-1-1.1 .4-.3 .1-.8 1-.2-.1-.9-.8-.1-.1-.2 7.1-7 .1-.5 .6-.2v-1.1h-1.8v1.1l.6 .2v.2l-8 8-.6 .2-.4-.1v1.6l.4-.2 .2 .2v5.2l-1.3 1.3h-2.4v-.5l-.2-.3v-2.5l-3.4-3.4h1.1l.2 .2 .8-.2 .2 .2 .8-.2 .2 .2 .8-.2 .2 .2 .8-.2 .2 .2 .8-.2 .4 .2v-1.6l-.4 .1-.4-.1v1.5h-.2v-1.5l-.4 .1-.4-.1v1.5h-.2v-1.5l-.4 .1-.4-.1v1.5h-.2v-1.5l-.4 .1-.4-.1v1.5h-.2v-1.5l-.4 .1-.4-.1v1.5h-.2v-.6h-.4v.5h-1.1l-1-1.1h1.1l.1 .2 1.3 .2v-.7l-.3-.1-.1-.5h-.8l-.2 .1v.8h-1.1l-.6-.5v-1l1.3-1.3h9.8l1.4-1.4v-3.4l-.2-.3v-.7l.2-.1 1.7 .1v.2a.98 .98 0 0 0 .4 1.6 .98 .98 0 0 0 1.2-.6 .98 .98 0 0 0-.6-1.3l-.3-.1-.1-1.1h-1.8l-.1 .6h-.6l-.4 .4-.8 .1-.1 1 .3 .2 .7 .1v3l-.2 .2-.2-.8-.9-.1-.1-1h-.7l-.2 .1-.2-.2v-1.2l.8-.1 .2-.3-.1-.8-.6-.2v-.2l.2-.1h2.3h-2.3l.2-.2h2.1l.4-.3 .1-.5 .2 .1h1.9v-1.9l1.1 1.2 .6 .1 .1 .6h1.9v-2.8h-2l-.5-.2 .4-.6h.2v.6h1.9v-1.3h-1.9l-1 .3-.3 .5 .1 .2 .3 .3a.17 .17 0 0 1 .1 .2 .17 .17 0 0 1-.3 .1l-.6 .1-.2-.2-3.2 .1v-.4l3.3 .1-.1-1.3-7.5 .1-.7 .3v-.6l-.3-.4 .3-.2 .9-.3 .4-.4 1.3 1.2 5.7 .1-.1-6.1h1.9v6.1h1.9v-2.9l.4 .3 .1 8.7 8 8.1h18.1v.2a.98 .98 0 0 0 .2 1.4 .98 .98 0 0 0 1.4-.2 .98 .98 0 0 0-.1-1.3l2.4-.1 .7-.5v-5.3l.2-.4a.5 .5 0 0 0-.1-.5 .5 .5 0 0 0-.6-.1h-.2v-3.1l-1.1-1.1 1.4-1.4 .3-.6v-5.9l-.3-.8-1.4-1.3v-.5a1.57 1.57 0 0 0-1.4-1.2h-1l-.7 .3-.4 .5-.2 .6a1.58 1.58 0 0 0 1.7 1.7l1.3 1.3v4.5l-.6 .7-8.3-.1v-1.3l1.1 .1 .4-.4h.4l.2 .4h.8l.3-.2v-.4h-.5v.6h-.2v-.6h-.6v.2h-.4v-.2h-.7v.6h-.2l.1-.7 .8-.1-.1-.5h.6l-.1 .5h1.3l-.1-.5 .1-.4 .1-1.6-.2-.3h-2.8l-.4 .4-.8-.7h-5l-1.5 1.2v7.8l.2 .3 3-.1 .1-.3v-1.3h2.1v.1l-1.8 1.8h-13v-.2h2.6l.2-.2v-8.9l-3.3-2.9 .1-1.2h3l.2-.2-.1-6.7-.2-.4-.4-.1h-7.8l-.2-.5h11.3l2.7 2.6v12.9l-.2 .4a.5 .5 0 0 0 .6 .5 .51 .51 0 0 0 .4-.3 .51 .51 0 0 0-.1-.6l-.1-13-3-3.1h-14.4l-4 3.9-3.3-3.3h1.4a2.37 2.37 0 0 0 3.3 0l-1.7-1.6-1.6 1.6h-1.4l-1.8-1.8h2.4l.2 .9 .5 .8 1.6-1.7h.3l1.6 1.7a2.3 2.3 0 0 0 .6-2h28.3v-.6l-.4 .1-.2 .5h-27.7l-.5-1.2h28.2l.2 .3 .4 .1v-.6h-.6v.2l-28.3-.1-1.6 1.6h-.3l-1.6-1.6-.5 .7-.2 .9h-2.4l-1.8-1.7h5l1.6 1.6 1.7-1.6-.3-.2h29.3v-.6l-.5 .1-.1 .5-28.8-.1a2.38 2.38 0 0 0-2.9 .3h-5zM88.1 80.4h.8v.3h-.8zM88.2 81.6h.8v.9h-.8zM88.2 83.3h.8v1h-.8zM89.8 83.4h.8v.9h-.8zM89.8 81.6h.8v.8h-.8zM90 80.4h.8v.3h-.8zM112.8 96.1h.7v.7h-.7z"/>
<path d="M113.9 95h.5v1.2h-.5zM114.9 95h.5v1.2h-.5zM115.9 95h.5v1.2h-.5zM115 92.1l.8-.8h.8l.2 .4 .5 .3h1.3l.4-.2 .2-.4-1.2-.1v.7h-.2v-.7h-2l.7-.6h.2l-.1 .4h2.6v-.4h1l-4 4.1-.6 .1-.6-.2zM116.9 95h.5v1.2h-.5zM117.9 95h.5v1.2h-.5zM118.9 95h.5v1.2h-.5zM119.9 95h.5v1.2h-.5zM120.9 95h.5v1.2h-.5zM120.3 92.4h.9v.8h-.9zM120.9 82.4l.3-.2 .5 .4 .6-.2h1.6v3l-.3-.1-2.7-2.7zM121.7 96.1h.7v.7h-.7z"/>
<path d="M122.2 92.4h.8v.8h-.8zM97.9 103.8h10.9l1.7-1.7h3.2l.2 .2 .8-.1 .2 .1 .8-.1 .2 .1 .8-.1 .2 .1 .8-.1 .7 .1 .3-.1 .3 .1v-1.6l-.4 .1-.4-.1v1.6h-.2v-1.6l-.4 .1-.4-.1v1.6h-.2v-1.6l-.4 .1-.4-.1v1.6h-.2v-1.6l-.4 .1-.4-.1v1.6h-.2v-1.6l-.4 .1-.4-.1v1.6h-.2v-.7h-.3v.5h-3.2l2-2 .2 1.1 1.3 .2v-.7h-.2l-.1-.5-1.1-.1 1.3-1.3h7.4l1.9-2 .1-4.3 .2-.2 1.6 .1v.2a.99 .99 0 0 0 .1 1.4 .99 .99 0 0 0 1.4-.1l.2 .1-.1 9.7h-3.6l-1.3 1.2-1.2-.1-.2-.2v-2.3l.3-.1 .8 .1 .1-1 1-.2v-.9h-.9l-.2 .5-.9 .1-.2-.1-.8 .1-.4-.1v1.6l.5-.1 .2 .2v2.2l-.3 .3-11.7-.1a.51 .51 0 0 0-.7-.1 .51 .51 0 0 0-.1 .7l.5 .2 .4-.2h13.9l1.3-1.2h2.3v.9h-.9v1l.9 .1 .2-.6 .8-.1 .6 .2 3.6 3.4h20.8l.1 .2-5.4 5.3-.2 .5a.61 .61 0 0 0 0 .9 .61 .61 0 0 0 .9-.1 .61 .61 0 0 0-.2-.9v-.1l5.5-5.5 12.9 .1a.63 .63 0 0 0-.4 1 .63 .63 0 0 0 1.1-.1h13.6l.5 .5a.61 .61 0 0 0 .5 .8 .61 .61 0 0 0 .7-.7 .61 .61 0 0 0-.8-.5l-.7-.6h-13.8l-.4-.4h18.4a.6 .6 0 0 0 .6 .6 .6 .6 0 0 0 .6-.5h.2l.8 .7h5.3l1 1.1v.9a.67 .67 0 0 0-.9 .2v.4l.2 .3-.1 .9-.8-.7h-14.8l-.1-.2a.54 .54 0 0 0-.8-.5 .54 .54 0 0 0 0 .9l-1.8 .1-.1-.1a.51 .51 0 0 0-.6-.4 .51 .51 0 0 0-.4 .6v.2h-.3l-.4-.5-.1-.6 1.2-1.2a.51 .51 0 0 0 .5-.5 .51 .51 0 0 0-.5-.5 .51 .51 0 0 0-.5 .7l-1.2 1.2v1.1l.5 .5-.4 .1a.56 .56 0 0 0-.9 0 .51 .51 0 0 0 0 .5 .51 .51 0 0 0 .5 .3l.3-.2h4.4l-.4 .7h-6.9l-.4-.5v-3.1l-.3-.5a.51 .51 0 0 0-.6-.5 .51 .51 0 0 0-.5 .6 .51 .51 0 0 0 .6 .5l.1 3.3 .9 .8h7.3l.5-.3a.52 .52 0 0 0 .5-.4 .52 .52 0 0 0-.2-.5l1.3-.1v1.6l-13.3 .1-1.9 1.7-.2 .6v1.6l-.7-1-.8-.1-1.3-.9v-2.6l-.3-.6-.4-.1h-3.8l-.3 .7v5.7l.1 .4 .6 .8h-1.9l-1.3 1.3v3l.2 .4a.5 .5 0 0 0 .5 .5l.4-.2v-.5l.4-.4-.2-1.2 .2-.1a1.2 1.2 0 0 0 1.7-1l-.1-.5-.4-.7h1.3l.7 .6v.8l.4 .2 .8-.1 .1-.9-.2-.3-.7-.1-.1-.1 1.5-.1-.2 .8 .8 .1-.8 .1v.4l.4 .3-.4 .6 .2 1.8 1 1 .1 .2-1 .1-.6-.5a.52 .52 0 0 0-.6-.3 .52 .52 0 0 0-.4 .5v.2l-.4 .3v.4h1.4l.2-.2 .2 .8 1 .2-.3 .5h-.6l-.2 .4 .1 .8 .7 .2 .4 .4-.1 .5h-.5l-.1 .2v4.1l.1 .2h.5v.2l-.5 .5h-3.5l-3.5-3.5a.59 .59 0 0 0-1 .1v-.7l.4-.4a.88 .88 0 0 0 1.1-.4h1.5l1.2 1.4 .1 2.8h2.1l.1-4.4-.2-.1h-1.9l-.3 .4-.2-.3v-1.4h1.7l.3 .3h.8l.4-.2v-.3h-.6v.5h-.2v-.5h-.6l-.1 .2h-1.7v-.4h3.2v-.4l-.2-.2h-.4v.6h-.2v-.6h-.3l-.3 .2-.1 .4h-1.7v-1l.9-.2 .2-.3h.7l.3 .4h.8l.3-.3v-.3h-.6v.6h-.2v-.6l-1.3 .2v-.2h-.5l-.1 .6h-.2l.1-.8h.7l-.3-.7 .3-.8h1.1l.8-.4v-1.1l-.7-.1 .7-.1v-.7l-.5-.2h-1.1l-.7 .7-.8 .1-.8 .8v6.4h-1.5a.88 .88 0 0 0-.8-1.2 .88 .88 0 0 0-.8 1.2l-.5 .7-.1 2.9-2 1.9v-2.5l-1.9-2 .4-.4 1.8-.1 .1-1 .6-.7v-5l-1.4-1.6h.9l2.6 2.7v1.4a.88 .88 0 0 0-.2 1.4 .88 .88 0 0 0 1.4-.2 .88 .88 0 0 0-.5-1.3l-.1-1.7-3-2.9h-5.7l-3 2.8-.8 .2-.1 .9 .4 .4v.8l-.9-.1-.1 .4h-.1v-.4l-.8-.1-6.6-6.6h5.8a.51 .51 0 0 0 .7 .4l.2-.2h1l2.3-2.4 .2 .1a.96 .96 0 0 0 .5 .8 .96 .96 0 0 0 1-.1h1.8a.93 .93 0 0 0 1.2 0l-.6-.6-.6 .6h-1.8l.4-.7h1.1l.2 .6 .6-.6-.6-.6-.2 .6h-1.1l-.3-.7-.7-.4 .3-.4v-.6l.5-.4 .2-.6 1.1 .1a.96 .96 0 0 0 1.4 .8l.1 .1v1.2l-.7-.1-.5 .2 1.4 1.4 .3-.9 .8 .4h.7l.1 .1a.77 .77 0 0 0-.4 .8 .77 .77 0 0 0 .5 .6 .76 .76 0 0 0 1-.5l-.2-.7-.7-.4 .6-.6 .3-.7a1.71 1.71 0 0 0-.8-1.7 1.71 1.71 0 0 0-2 .2v-.2a.97 .97 0 0 0-.9-1l-.7 .3-.3 .6h-1.1a.96 .96 0 0 0-.8-.9l-.5 .1-.3 .2a1.03 1.03 0 0 0 .4 1.7v.3l-1.6 1.6h-.2l-.2-.5-1.4 1.3 .6 .4-.7 .7h-.7a.51 .51 0 0 0-.8 0l-.1 .3h-5.8l-1.9-1.9 .3-.2 .6 .1a.5 .5 0 0 0 .8-.2l-.1-.5a.27 .27 0 0 1-.2-.3 .27 .27 0 0 1 .3-.2h1l2.2 2.4a.5 .5 0 0 0 .6 .5 .52 .52 0 0 0 .4-.6 .52 .52 0 0 0-.6-.4l-2.3-2.3h3.2l.2 .7 .8 .9a.8 .8 0 0 0-.8 .4 .8 .8 0 0 0 .1 .9l.5 .3a.77 .77 0 0 0 .8-.8l-.4-.8h.8l.8-.4 .3 .9 1.3-1.4a.98 .98 0 0 0-1.1-.1v-1.2l.1-.1a.96 .96 0 0 0 1.4-.8 .97 .97 0 0 0-.9-1l-.4 .1a.95 .95 0 0 0-.6 1l-.1 .1a1.67 1.67 0 0 0-1.8-.2 1.67 1.67 0 0 0-1 1.5l-4.5-.1-.7-.4a.52 .52 0 0 0-.1-.7 .52 .52 0 0 0-.8 .1 .62 .62 0 0 0-1 0l-6.6-.1v1.3l7.5-.1 .7-.3v.6l.3 .4-.2 .2h-.5a.51 .51 0 0 0-.9 0l-.1 .1-.7-.2-.4-.4-5.7-.1v6.1h-1.9l.1-6.1h-1.9v1.7l-.2 .2a.64 .64 0 0 0-.8-.7l-.2-.1v-2.4l1.2 1.1h1.9l-.1-1.3h-1.8l-.1 .4-.4-.4 .4-.2h2v-2.8h-1.9l-.1 .3h-.8v-2.5l.3-.2a.51 .51 0 0 0-.2-.7 .51 .51 0 0 0-.7 .1v1.5l-1.2-1.1h-14.5a.51 .51 0 0 0-.5-.2 .51 .51 0 0 0-.4 .4l-2.3 .2a.61 .61 0 0 0-.4 .7h-.3l-.5-.4v-.7l1.1-1.1h.2a.52 .52 0 0 0 .4-.6 .52 .52 0 0 0-.7-.4 .52 .52 0 0 0-.3 .6l-1.2 1.3v1l.5 .6-.4 .1-.3-.3h-.5v-2l1-.1 .1-.5-1.5-.1 1.5-.1-.1-.5h-1l-.1-.2 1.1-.1 .1-.5-1.5-.1 1.5-.1-.1-.5h-1l-.1-.2 1.1-.1 .2-.3h10.3l.5 .2 .4-.2h6.6l4.5 4.4v.9l-.7 .2v1.1h1.9l-.1-1.1-.6-.2v-.5l.2-.1 1.3 1.2 .9 .1 .1 .6h1.8l.1-.6 .6-.1 .4-.3h.7l.3-.4-.1-.7-.3-.3-.1-1.1-.3-.4a.56 .56 0 0 0-.6-.7l-.4 .3v.2a.5 .5 0 0 0 .5 .5l.3 .3v.9l-.4 .3v.7l-.2 .2-1.7-.1 .3-1 .3 .1a.5 .5 0 0 0 .8-.3 .5 .5 0 0 0-.6-.6l-.7-.7h-1.1l-1.7 1.4-2.8-3 7.9-.1 .2 .7 1 .1v1h.7l.2-.1 .2 .2v1.2l-.9 .2-.1 .8 .3 .4h.9l.1 .1-.7 .7h-.8l-.6 .5-3.5-.1v2.8l3.1-.2 .8-.6 .2 .4 .5 .2 1.1-.1 .4-.5h3.5l.4 .6h1.2l.4-.3 .1-.3h-1v.6h-.2v-.6h-5.3l-.1 .6h-.2v-.7l1.2-.1-.2-.5 .1-.1 3.7-.1 .1 .2-.2 .5h2.1l-.1-.4-.3-.2-.6-.1v.7h-.2v-.7h-.7l1.7-1.7h3.3a3.2 3.2 0 0 0 4.4 0l-2.2-2.2-2.2 2.2h-3.3l.4-.5v-1.9h1.9l.2 1.1 .7 1.2 2.1-2.2h.3l2.2 2.2a3.1 3.1 0 0 0 0-4.4l-2.2 2.2h-.3l-2.1-2.2a3.1 3.1 0 0 0-.9 2.1h-1.9l.2-1.9h.9l.1-.3h1.7l2.2 2.1 2.2-2.1a3.2 3.2 0 0 0-4.4 0h-1.7v-.7l-.2-.1h-.8l-.1 .5-.8 .2-.3-.2-.8 .2-.2-.2-.8 .2-.2-.2-.8 .2-.8-.2-.2 .2-.6-.2-.9-.8h-2.5l-.4 .1h-7.8l-3.1-3h-9.6l-.3-.2a.53 .53 0 0 0-.3-.6 .53 .53 0 0 0-.6 .1v.1a.5 .5 0 0 0 0 .5 .5 .5 0 0 0 .5 .2l.1 .2h-7l-.3-.5zM124.1 80.4h1.5v.3h-1.5zM124.1 80.9h1.5v.3h-1.5zM124.1 81.4h1.5v.3h-1.5zM124.1 81.9h1.5v.3h-1.5zM124.1 82.4h1.5v.3h-1.5zM124.1 82.9h1.5v.3h-1.5zM124.1 83.4h1.5v.3h-1.5zM124.1 83.9h1.5v.3h-1.5zM124.1 84.4h1.5v.3h-1.5zM124.1 84.9h1.5v.3h-1.5z"/>
<path d="M124.1 85.4h1.5v.3h-1.5zM124.1 85.9h1.5v.3h-1.5zM124.1 86.4h1.5v.3h-1.5zM124.1 86.9h1.5v.3h-1.5zM124.1 87.4h1.5v.3h-1.5zM124.1 87.9h1.5v.3h-1.5zM124.1 88.4h1.5v.3h-1.5zM124.1 88.9h1.5v.3h-1.5zM124.1 89.4h1.5v.3h-1.5zM124.1 89.9h1.5v.3h-1.5zM124.1 90.4h1.5v.3h-1.5zM124.1 90.9h1.5v.3h-1.5z"/>
<path d="M124.1 91.4h1.5v.3h-1.5zM124.1 91.9h1.5v.3h-1.5zM127.8 80.4h1.5v.3h-1.5zM127.8 80.9h1.5v.3h-1.5zM127.8 81.4h1.5v.3h-1.5zM127.8 81.9h1.5v.3h-1.5zM127.8 82.4h1.5v.3h-1.5zM127.8 82.9h1.5v.3h-1.5zM127.8 83.4h1.5v.3h-1.5zM127.8 83.9h1.5v.3h-1.5zM127.8 84.4h1.5v.3h-1.5zM127.8 84.9h1.5v.3h-1.5z"/>
<path d="M127.8 85.4h1.5v.3h-1.5zM127.8 85.9h1.5v.3h-1.5zM127.8 86.4h1.5v.3h-1.5zM127.8 86.9h1.5v.3h-1.5zM127.8 87.4h1.5v.3h-1.5zM127.8 87.9h1.5v.3h-1.5zM127.8 88.4h1.5v.3h-1.5zM127.8 88.9h1.5v.3h-1.5zM127.8 89.4h1.5v.3h-1.5zM127.8 89.9h1.5v.3h-1.5zM127.8 90.4h1.5v.3h-1.5zM127.8 90.9h1.5v.3h-1.5z"/>
<path d="M127.8 91.4h1.5v.3h-1.5zM127.8 91.9h1.5v.3h-1.5zM132.3 86h2.9v5.4h-2.9zM142.2 86h2.9v5.4h-2.9zM147.9 83.4h.9v.8h-.9zM147.9 85.2h.9v.8h-.9zM147.9 90.7h1v3.2h-1zM147.9 95.8h1v3.1h-1zM142.2 83.5l1.3-1h4.9l.7 .7v4.4l-3.2 .1-.8 .5-.1 3.2-2.9-.1zM149.6 83.4h.9v.8h-.9zM149.6 85.2h.9v.8h-.9zM149.1 97.1l.7-.6 .4-.2 .1 2.9h-1.3z"/>
<path d="M150 78.2h3.2v2.5h-3.2zM150.5 90.7h1v3.2h-1zM150.5 95.8h1v3.1h-1zM151.5 83.3h.8v.9h-.8zM151.5 85.2h.8v.8h-.8zM149.6 82.9l2.8-.1v.2l-.2 .1v1.3l.2 .2-2.7 .1v-.3h.8l.3-.4h.4l.2 .3 .3 .1-.1-.4h-1.2l-.1 .4h-.5v-.9h1.8l.1-.4-.3 .1-.2 .3h-.4l-.1-.3-.3-.1-.1 .4h-.5v-.4l-.2-.1zM153 90.7h1v3.2h-1zM153 95.8h1v3.1h-1zM154 90.4h1.5l-.2 .3v1.3l-1 .5-.1-.1v-1.7zM155.5 90.7h1v3.2h-1zM155.5 95.8h1v3.1h-1zM158.1 90.7h1v3.2h-1z"/>
<path d="M158.1 95.8h1v3.1h-1zM145.6 92.6l2-1.9 .2 3.3 1.1 .1 .2-.2h1.1l.2 .2h1.1l.1-.2v-1.5h-.6v1.7h-.1l-.1-1.7h-.6v1.5h-1.1v-3.1l1.1-.1 .1 1.5h1.3l.1-1.4 .6-.1 .5 .5v2.7l.1 .2h1.2l.1-1 .6 .2 .5-.3 .1 1 1.2 .1 .1-.2v-1.3l.2-.1 .4 .4 .6-.1v1.2l1.2 .1 .2-.2v-3.2l-.2-.3h.4l.8 .8v7.7l-.7 .7h-5.1l-.4-.4 .2-3.2 1 1v1.9l.2 .2h1.2l.1-1.6 .5 .4 .6-.1 .1 1.3h1.2v-3.5h-1.3v1.4a.84 .84 0 0 0-1.1 .2l-.2-1.6h-1.1l-.3 .5-1.5-1.4h-6.1zM164.1 80.4l.8-.1v.3h-.8zM164.2 81.7h.8v.9h-.8zM164.2 83.4h.8v.9h-.8zM166 80.4l.8-.1v.3h-.8zM166 83.5h.8v.8h-.8zM166 81.7h.8v.8h-.8zM188.9 96h.7v.7h-.7zM189.9 95h.5v1.2h-.5zM190.9 95h.5v1.2h-.5zM191.9 95h.5v1.2h-.5z"/>
<path d="M191.5 91.6l.3-.3h.9l.3 .5 .9 .1v-.6h-2.1l.7-.7 .3 .1-.1 .4h2.5v-.5l.7 .1-.6 .6h-1.2v.6h.4v.2l-2.8 2.8-.2-.2zM192.9 95h.5v1.2h-.5zM193.9 95h.5v1.2h-.5zM194.9 95h.5v1.2h-.5zM195.9 95h.5v1.2h-.5zM196.9 95h.5v1.2h-.5zM196.4 92.4h.8v.8h-.8zM196.9 82.4l.4-.2 .5 .4 .5-.3h1.6v3h-.2zM197.8 96h.7v.7h-.7zM198.2 92.4h.8v.8h-.8zM200.2 80.4h1.5v.3h-1.5zM200.2 80.9h1.5v.3h-1.5z"/>
<path d="M200.2 81.4h1.5v.3h-1.5zM200.2 81.9h1.5v.3h-1.5zM200.2 82.4h1.5v.3h-1.5zM200.2 82.9h1.5v.3h-1.5zM200.2 83.4h1.5v.3h-1.5zM200.2 83.9h1.5v.3h-1.5zM200.2 84.4h1.5v.3h-1.5zM200.2 84.9h1.5v.3h-1.5zM200.2 85.4h1.5v.3h-1.5zM200.2 85.9h1.5v.3h-1.5zM200.2 86.4h1.5v.3h-1.5zM200.2 86.9h1.5v.3h-1.5z"/>
<path d="M200.2 87.4h1.5v.3h-1.5zM200.2 87.9h1.5v.3h-1.5zM200.2 88.4h1.5v.3h-1.5zM200.2 88.9h1.5v.3h-1.5zM200.2 89.4h1.5v.3h-1.5zM200.2 89.9h1.5v.3h-1.5zM200.2 90.4h1.5v.3h-1.5zM200.2 90.9h1.5v.3h-1.5zM200.2 91.4h1.5v.3h-1.5zM200.2 91.9h1.5v.3h-1.5zM203.9 80.4h1.5v.3h-1.5zM203.9 80.9h1.5v.3h-1.5z"/>
<path d="M203.9 81.4h1.5v.3h-1.5zM203.9 81.9h1.5v.3h-1.5zM203.9 82.4h1.5v.3h-1.5zM203.9 82.9h1.5v.3h-1.5zM203.9 83.4h1.5v.3h-1.5zM203.9 83.9h1.5v.3h-1.5zM203.9 84.4h1.5v.3h-1.5zM203.9 84.9h1.5v.3h-1.5zM203.9 85.4h1.5v.3h-1.5zM203.9 85.9h1.5v.3h-1.5zM203.9 86.4h1.5v.3h-1.5zM203.9 86.9h1.5v.3h-1.5z"/>
<path d="M203.9 87.4h1.5v.3h-1.5zM203.9 87.9h1.5v.3h-1.5zM203.9 88.4h1.5v.3h-1.5zM203.9 88.9h1.5v.3h-1.5zM203.9 89.4h1.5v.3h-1.5zM203.9 89.9h1.5v.3h-1.5zM203.9 90.4h1.5v.3h-1.5zM203.9 90.9h1.5v.3h-1.5zM203.9 91.4h1.5v.3h-1.5zM203.9 91.9h1.5v.3h-1.5zM208.3 86h2.9v5.4h-2.9zM218.2 86h2.9v5.4h-2.9z"/>
<path d="M223.9 85.1h1v.8h-1zM223.9 83.3h1v.8h-1zM224 90.7h1v3.1h-1zM224 95.7h1v3.2h-1zM218.2 83.5l1.3-1h5l.7 .7-.1 4.4-3.2 .1-.8 .5-.1 3.1h-2.8zM225.7 85.1h.9v.8h-.9zM225.7 83.3h.9v.8h-.9zM208.5 92.7h13.3l1.8-1.7 .2 .1v2.9h1.2l.2-.2h1.1l.2 .2h1.1l.1-.2v-1.4h-.6v1.6h-.2v-1.6h-.6v1.4h-1.1v-3.1l1-.1 .1 1.6 1.4-.1 .1-1.2 1 1v1.9l.2 .2h1.1l.3-.7a.53 .53 0 0 0 .8 .2l.2-.1 .1 .6h1.1l.2-.1v-.4h.2a.5 .5 0 0 0 .7-.1l.2-.1 .1 .7h1.3v-3.1l.2-.1 .1 .1v8h-.3v-3.2l-.1-.2h-1.1l-.2 .2v2a.57 .57 0 0 0-.9 0l-.2-.1v-1.9l-.1-.2h-1.2l-.2 .5-1.2-1h-6.2l-.5 .5v3.1l-.5 .5h-8.1l-6.3-6.3zM226.1 78.1h3.1v2.6h-3.1zM226.5 90.7h1v3.1h-1zM226.5 95.7h1v3.2h-1zM227.6 83.3h.8v.8h-.8z"/>
<path d="M227.6 85.1h.8v.8h-.8zM225.7 82.8h2.7l.1 .2h-.3v1.4l.2 .2h-2.7v-.2h.8l.4-.4h.4l.1 .3 .3 .1v-.4h-1.3v.4h-.5v-1h1.8v-.4l-.3 .1-.1 .3h-.4l-.2-.2-.3-.2v.4h-.5v-.4h-.2zM227.7 95.5l1.2 .1-.1 3.3 .2 .2h1l-.4 .7-3.8-.1 .4-.7 1.3 .1 .2-.1zM229 90.7h1v3.1h-1zM229 95.7h1v3.2h-1zM225.8 85h2.8l.3-.3v-.4l.4-.3h.6l.4 .3v2.9l-.3 .3h-4.4l-.1-.2v-2zM231.6 90.7h1v3.1h-1zM231.6 95.7h1v3.2h-1zM234.1 90.7h1v3.1h-1zM234.1 95.7h1v3.2h-1zM228.1 90.3h6.9l-.1 .2h-.9l-.1 1.6-.5 .4-.5 .2-.1-2.1-.2-.1h-1.1l-.2 2.2a.79 .79 0 0 0-1 .1l-.1-2.3h-1.2l-.3 .5zM87.9 103.3h3.3v1.8h-3.3z"/>
<path d="M87.9 113h3.3v1.8h-3.3zM93.4 106.4h2.4v.8h-2.4zM93.4 107.9h2.4v.8h-2.4zM93.4 109.4h2.4v.8h-2.4zM93.4 110.9h2.4v.8h-2.4zM98.1 118.7l3.2-.1 .8-.5v-3.1h2.9v7.8l-1.3 1h-5l-.7-.7zM102.1 114.9h2.9v5.4h-2.9zM112.8 100.4h.7v.7h-.7zM94.9 107.5l1-.1 .2-.3h16.7l.9 .8-.1 .2-6.3-.1a.54 .54 0 0 0-.9 .1h-10.3l-.2-.4h-1zM113.9 100.9h.5v1.2h-.5zM112.1 115h2.8v8.1l2.3 2.6v3.5l.2 .3 .4 .1h5.6l.1 .2v1.1h-7.7l-.5-.5v-3.9l-3.3-2.7zM114.9 100.9h.5v1.2h-.5z"/>
<path d="M112 114.9h2.9v5.4h-2.9zM115.9 100.9h.5v1.2h-.5zM116.9 100.9h.5v1.2h-.5zM116.8 116.6h.8v.8h-.8zM117.9 100.9h.5v1.2h-.5zM118.9 100.9h.5v1.2h-.5zM117.9 119.6h1.5v.3h-1.5zM117.9 119.1h1.5v.3h-1.5zM117.9 118.6h1.5v.3h-1.5zM117.9 118.1h1.5v.3h-1.5zM117.9 117.6h1.5v.3h-1.5zM117.9 117.1h1.5v.3h-1.5z"/>
<path d="M117.9 116.6h1.5v.3h-1.5zM117.9 116.1h1.5v.3h-1.5zM117.9 115.6h1.5v.3h-1.5zM117.9 115.1h1.5v.3h-1.5zM117.9 114.6h1.5v.3h-1.5zM117.9 114.1h1.5v.3h-1.5zM119.9 100.9h.5v1.2h-.5zM120.9 100.9h.5v1.2h-.5zM121.7 100.4h.7v.7h-.7zM121.6 119.6h1.5v.3h-1.5zM121.6 119.1h1.5v.3h-1.5zM121.6 118.6h1.5v.3h-1.5z"/>
<path d="M121.6 118.1h1.5v.3h-1.5zM121.6 117.6h1.5v.3h-1.5zM121.6 117.1h1.5v.3h-1.5zM121.6 116.6h1.5v.3h-1.5zM121.6 116.1h1.5v.3h-1.5zM121.6 115.6h1.5v.3h-1.5zM121.6 115.1h1.5v.3h-1.5zM121.6 114.6h1.5v.3h-1.5zM121.6 114.1h1.5v.3h-1.5zM124.2 113.1h.8v.8h-.8zM124.7 109.6h.7v.7h-.7zM124.7 105.3h.7v.7h-.7z"/>
<path d="M126 113.1h.8v.8h-.8zM125.8 110.1h.5v1.2h-.5zM125.8 104.2h.5v1.2h-.5zM126.8 110.1h.5v1.2h-.5zM126.8 104.2h.5v1.2h-.5zM127.8 110.1h.5v1.2h-.5zM127.8 104.2h.5v1.2h-.5zM128.8 110.1h.5v1.2h-.5zM128.8 104.2h.5v1.2h-.5zM129.8 110.1h.5v1.2h-.5zM129.8 104.2h.5v1.2h-.5zM130.8 110.1h.5v1.2h-.5z"/>
<path d="M130.8 104.2h.5v1.2h-.5zM131.3 111.5l.2-.1 .3 .2-.1 3.1-1 1-.3-.1 .1-.4h-2.5l.1 .4-.7 .1 .5-.7h2.6l-.2-.4-.4-.2h-.6v.6h-.2v-.6l-.4-.2zM131.8 110.1h.5v1.2h-.5zM131.8 104.2h.5v1.2h-.5zM132.8 110.1h.5v1.2h-.5zM132.8 104.2h.5v1.2h-.5zM133.6 109.6h.7v.7h-.7zM133.6 105.3h.7v.7h-.7zM154.4 115.5l.4-.1h3.4l.5 .2v3.1l1.4 .9 .8 .1 .5 1v5.1l-.1 .4-.5 .3-1.5 .1-.9-.1-.2-.2-.1-.6 .2-.3 1.1-.2v-1.5l-.5-.5h-2.7l-.4-.4h-.5l-.9-.9-.1-6zM168.5 118.9h4.3l.2 .1v2l-.3 .3h-2.9l-.3 .3v.4l-.3 .4h-.7l-.3-.4v-2.8zM173.3 118.8l3.2-.1 .8-.5v-3.1l2.9-.1v7.9l-1.3 .9h-5l-.6-.6zM177.3 115h2.9v5.4h-2.9z"/>
<path d="M164.1 119.5l.7-.6h8.2v1.4l-.6-.1v.7h-.8v.6h-.5v-.6h-1.3l.2 .6-.2 .3v1.7l.1 .2 2.8 .1 .4-.4 .9 .7h4.9l1.6-1.3v-7.9h6.5l.1 9 3.2 2.8-.1 1.3h-3l-.2 .1v5.5l.1 1.2 .1 .3 .6 .3 7.7-.1 .4 .5 .5 .3 4.5-.1 1.6 1.6 1.7-1.6a2.38 2.38 0 0 0-3.3 0h-3.9l.5-.6 1-.1 .5-.5v-1.6l-.3-.5 .3-.4v-2.5l-.4-.4 .1-.8-.2-.7h-2.8l-.5-.5h1.4v.5h3.4v-1.8h-1.5l.3-.2h3.7a.5 .5 0 0 0 .6 .5l.6-.4 4.7 4.7 1.4 .1-.1 .2-.9 .1-2.3 2.3-.1 1.6 2.8 2.9 .2 .4 .3 .2 1.7-.1-.1-.3-.3-.3 .4-.3 .1-.4h-1.5v.3l-.3 .1-.5-.6h2.3l-.1-.3-.4-.3 .3-.3 .1-.4h-1.4v.4l.4 .3-.4 .3v.3h-.8l-2.2-2.1 .1-.2 .2 .1a.5 .5 0 0 0 .8-.2v-.2h1.9l.4 .4-.4 .4v.3h1.4l-.1-.3-.4-.3 .5-.4 .1-.3-3.4 .2-.2-.4h3.6l-.3-.5-.4-.1v.6h-.2v-.6l-.5 .1-.1 .5h-2.1v-.3l1.2-1.2 .6-.2 .1 .5 .4 .3 .7-.1 .3-.3h3l.2-.1v-.6l-3.2 .1-.1-.4 3.3 .1 .8-.8 1.8 1.7 1.2 .1-.4 .5h-1.3l-.9 .9-.3-.5h-1l-1 .3-.2-.3-.3-.3-1 .1-.1 .9 .5 .5-.4 .4v.7l.4 .4-.5 .4 .1 .8 .3 .3-.3 .4v.6l.4 .4 .1 .6-2.1 .1-1.1-1.1h.9l.2 .4h.8l.3-.2 .1-.4h-.6v.6h-.2v-.6h-.6v.2h-.9l-6.2-6.2 .1-.2a.5 .5 0 0 0-.4-.8 .5 .5 0 0 0-.5 .6l.2 .7 7.3 7.4v.1h-30v-.9h21.3a2.37 2.37 0 0 0 3.3 0l-1.7-1.6-1.6 1.6h-21.3v-1.8h20.5l.2 .9 .5 .8 1.6-1.7h.3l1.6 1.7a2.38 2.38 0 0 0 0-3.3l-1.6 1.6h-.3l-1.6-1.6-.5 .7-.2 .9h-20.5v-.6h-7.1l4.9-.2 2.7-2.5 .3-.8v-5.4l-.1-.2h-4.9l-.7 .2-.5 .5-1.6-1.6v-1.3l-.3-.4h-3l-.3 .2v2.7l.3 .2h1.3l1.1 1.1-.2 .1-1.3-.1-.7 .3-.5 .8v1a1.55 1.55 0 0 0 1.3 1l1.3-.1 .6-.4 .4-.6 .1-1 1.5 1.4-.1 1.4h-3.1l-1.7 1.6-.2 .7v.7l.3 .4-.3 .6-.1 3h-21.6l-.1-.1 3.1-3.1 .1-1.1 .1-.1a.93 .93 0 0 0 1.1 .2l2.9 2.8 4.2 .1 1.1-1 .1-.5 .5-.1 .1-.2v-4.2l-.6-.2v-.8l-.6-.6v-.2h4a1.56 1.56 0 0 0 1.8 1.4h.2a1.52 1.52 0 0 0 1.7-1.5h-1.7v1.5h-.2v-1.5l-5.8 .1 .2-.3h7.5a1.54 1.54 0 0 0-1.4-1.4h-.3v1.4h-.2v-1.4a1.54 1.54 0 0 0-1.8 1.4h-3.8l.5-.6v-2.1l-.3-.5a.56 .56 0 0 0 .4-.9l1.3-.6 .3-1.3 1.6 1.8 .1 .7a1.55 1.55 0 0 0 1.3 1l1.3-.1 .6-.4 .4-.7-.1-.9a1.56 1.56 0 0 0-1.3-1h-.3l-1.3-1.3v-3.4h8.1v-.5l-.5 .1-.1 .4h-.5v-.3l-.3-.3h-.2v.6h-.2v-.6l-.5 .2-.1 .4h-5.7zM188.9 100.3h.7v.7h-.7zM189.9 100.9h.5v1.2h-.5zM187.3 115.1h2.8v8.1l2.3 2.5v3.6l.2 .3 .5 .1h5.5l.2 .1-.1 1.2h-7.7l-.5-.5v-3.9l-3.2-2.8zM187.2 115h2.9v5.4h-2.9zM188.7 108.8l2.1-.1 .6 .7-2.2 .1-.6-.5zM190.9 100.9h.5v1.2h-.5zM191.9 100.9h.5v1.2h-.5zM192.9 100.9h.5v1.2h-.5zM193.9 100.9h.5v1.2h-.5zM193.1 119.7h1.5v.3h-1.5zM193.1 119.2h1.5v.3h-1.5z"/>
<path d="M193.1 118.7h1.5v.3h-1.5zM193.1 118.2h1.5v.3h-1.5zM193.1 117.7h1.5v.3h-1.5zM193.1 117.2h1.5v.3h-1.5zM193.1 116.7h1.5v.3h-1.5zM193.1 116.2h1.5v.3h-1.5zM193.1 115.7h1.5v.3h-1.5zM193.1 115.2h1.5v.3h-1.5zM193.1 114.7h1.5v.3h-1.5zM193.1 114.2h1.5v.3h-1.5zM194.9 100.9h.5v1.2h-.5zM195.9 100.9h.5v1.2h-.5z"/>
<path d="M196.9 100.9h.5v1.2h-.5zM197.8 100.3h.7v.7h-.7zM196.8 119.7h1.5v.3h-1.5zM196.8 119.2h1.5v.3h-1.5zM196.8 118.7h1.5v.3h-1.5zM196.8 118.2h1.5v.3h-1.5zM196.8 117.7h1.5v.3h-1.5zM196.8 117.2h1.5v.3h-1.5zM196.8 116.7h1.5v.3h-1.5zM196.8 116.2h1.5v.3h-1.5zM196.8 115.7h1.5v.3h-1.5zM196.8 115.2h1.5v.3h-1.5z"/>
<path d="M196.8 114.7h1.5v.3h-1.5zM196.8 114.2h1.5v.3h-1.5zM199.4 113.2h.8v.8h-.8zM199.9 109.6h.7v.7h-.7zM199.9 105.3h.7v.7h-.7zM201.2 113.2h.9v.8h-.9zM201 110.2h.5v1.2h-.5zM201 104.3h.5v1.2h-.5zM202 110.2h.5v1.2h-.5zM202 104.3h.5v1.2h-.5zM203 110.2h.5v1.2h-.5zM203 104.3h.5v1.2h-.5z"/>
<path d="M204 110.2h.5v1.2h-.5zM204 104.3h.5v1.2h-.5zM205 110.2h.5v1.2h-.5zM205 104.3h.5v1.2h-.5zM206 110.2h.5v1.2h-.5zM206 104.3h.5v1.2h-.5zM206.5 111.6l.3-.1 .2 .2v3l-1.1 1h-.3l.2-.4h-2.6l.1 .4h-.7l.5-.6h2.7l-.2-.4-.5-.3h-.5v.7h-.2v-.7l-.5-.1zM207 110.2h.5v1.2h-.5zM207 104.3h.5v1.2h-.5zM208 110.2h.5v1.2h-.5zM208 104.3h.5v1.2h-.5zM208.8 109.6h.7v.7h-.7z"/>
<path d="M208.8 105.3h.7v.7h-.7zM226.1 115.6l.3-.1 4.9 .1 .3 .4v2.5l3.8 1.1 .9 .1 .7 .5 .1 .3v5.3l-.2 .4a1.47 1.47 0 0 1-1.6 .4l-1.7-.1a.51 .51 0 0 1-.1-.8l.2-.4h1.3v-1.5l-.9-.5-2.3-.2-1-.9-4.4-.3-.4-.2-.1-5.7zM94.8 122.2h.8v.8h-.8zM94.8 120.4h.8v.8h-.8zM95.5 132.4h.8v.8h-.8zM95.5 134.2h.8v.9h-.8zM93.9 124.6h3.2v2.6h-3.2zM94.8 121.7h2.7l.2 .3v1.2l-.3 .3h-2.6l-.2-.4v-1zM93.1 124.5l.7-.3 7.4 .1a.8 .8 0 0 1 .8 .8v2.3l.7 .7h1.3a1 1 0 0 1 1 1v6.6a1.05 1.05 0 0 1-1 1.1l-4.4-.1a1 1 0 0 1-1-1v-5.6l-.6-2.3h-4.2a1 1 0 0 1-1-1v-1.8zM96.6 120.4h.9v.8h-.9zM96.6 122.2h.9v.8h-.9zM97.1 132.7h1v.8h-1z"/>
<path d="M97.1 134.2h1v.8h-1zM95 132.1l3.2-.1 .1 .2v1.6l-.2 .1h-3zM98.3 120.4h1v.8h-1zM98.3 122.2h1v.8h-1zM98.9 132.7h.9v.8h-.9zM98.9 134.2h.9v.8h-.9zM102.1 128.1h2.9v5.4h-2.9zM112.2 128.3l.3-.2h1.9l.4 .3 .1 4.8h2.5l.7-.4h5.1l.4 .4v1.5l-.4 .4h-.8a1.12 1.12 0 0 0-1.7-.9l-.5 .9-7.9-.1-.3-.4v-5.9zM112 128.1h2.9v5.4h-2.9zM117.4 125.9l.4 .3v.2h-.1v.3h.1l-.1 .5h.1v.2h-.1l-.2 1.9-.1-.2zM115.3 131.3l.2-.2h7.9l.1 .2v.9l-.1 .1h-5.6l-.4 .3h-1.8l-.3-.2zM117.9 133.6h1.5v.3h-1.5z"/>
<path d="M117.9 133.1h1.5v.3h-1.5zM117.9 132.6h1.5v.3h-1.5zM117.9 132.1h1.5v.3h-1.5zM117.9 131.6h1.5v.3h-1.5zM117.9 131.1h1.5v.3h-1.5zM117.9 130.6h1.5v.3h-1.5zM117.9 130.1h1.5v.3h-1.5zM117.9 129.6h1.5v.3h-1.5zM117.9 129.1h1.5v.3h-1.5zM117.9 128.6h1.5v.3h-1.5zM117.9 128.1h1.5v.3h-1.5zM117.9 127.6h1.5v.3h-1.5z"/>
<path d="M117.9 127.1h1.5v.3h-1.5zM117.9 126.6h1.5v.3h-1.5zM117.9 126.1h1.5v.3h-1.5zM117.9 125.6h1.5v.3h-1.5zM117.9 125.1h1.5v.3h-1.5zM117.9 124.6h1.5v.3h-1.5zM117.9 124.1h1.5v.3h-1.5zM117.9 123.6h1.5v.3h-1.5zM117.9 123.1h1.5v.3h-1.5zM117.9 122.6h1.5v.3h-1.5zM117.9 122.1h1.5v.3h-1.5zM117.9 121.6h1.5v.3h-1.5z"/>
<path d="M117.9 121.1h1.5v.3h-1.5zM117.9 120.6h1.5v.3h-1.5zM117.9 120.1h1.5v.3h-1.5zM118 127.7l1.9-.1 .3 .1v.4h4.2l.4 .4v.5l-.2 .3-.3 .1h-6.1l-.4-.3v-1zM117.8 126.1l7-.1v1.8h-3.4v-.4h-3.6zM121.6 133.6h1.5v.3h-1.5zM121.6 133.1h1.5v.3h-1.5zM121.6 132.6h1.5v.3h-1.5zM121.6 132.1h1.5v.3h-1.5zM121.6 131.6h1.5v.3h-1.5zM121.6 131.1h1.5v.3h-1.5zM121.6 130.6h1.5v.3h-1.5z"/>
<path d="M121.6 130.1h1.5v.3h-1.5zM121.6 129.6h1.5v.3h-1.5zM121.6 129.1h1.5v.3h-1.5zM121.6 128.6h1.5v.3h-1.5zM121.6 128.1h1.5v.3h-1.5zM121.6 127.6h1.5v.3h-1.5zM121.6 127.1h1.5v.3h-1.5zM121.6 126.6h1.5v.3h-1.5zM121.6 126.1h1.5v.3h-1.5zM121.6 125.6h1.5v.3h-1.5zM121.6 125.1h1.5v.3h-1.5zM121.6 124.6h1.5v.3h-1.5z"/>
<path d="M121.6 124.1h1.5v.3h-1.5zM121.6 123.6h1.5v.3h-1.5zM121.6 123.1h1.5v.3h-1.5zM121.6 122.6h1.5v.3h-1.5zM121.6 122.1h1.5v.3h-1.5zM121.6 121.6h1.5v.3h-1.5zM121.6 121.1h1.5v.3h-1.5zM121.6 120.6h1.5v.3h-1.5zM121.6 120.1h1.5v.3h-1.5zM123.3 121h.2l2.8 2.8-.1 .1-.4 .2a.5 .5 0 0 0-.8-.2l-.1 .1-1.6-.1zM124 120.6h2.9l.4 .3 .5 .1 7.9 8-1 .2-.2 1-1.1-.1zM135 138.1h.9v.8h-.9z"/>
<path d="M135 135.1h.9v.8h-.9zM134.9 131.1h.8v.9h-.8zM134.9 129.3h.8v.8h-.8zM135 133.5h1v.9h-1zM135 136.6h1v.8h-1zM136.9 138.1h.8v.8h-.8zM136.9 135.1h.8v.8h-.8zM137.5 132.1h1.5v.3h-1.5zM137.5 131.6h1.5v.3h-1.5zM137.5 131.1h1.5v.3h-1.5zM137.5 130.6h1.5v.3h-1.5zM137.5 130.1h1.5v.3h-1.5z"/>
<path d="M136.8 133.5h.9v.9h-.9zM136.8 136.6h.9v.8h-.9zM138.5 134.5l.3-.2 .1 .2 .8 .1-.1 .1-.7 .1 .2 .9h.6l.9 .9h1.8l.7 .7v1l-.7 .4-.1 .6-.3-.1v-.4l-.2-.4 .4-.3v-.4h-1.4l-.1 .4-.2-.1v-.5h1.7v-.3l-.4-.2h-.2v.5h-.2v-.5l-.5 .1-.2 .4h-.2l-.1-.3-.3-.2h-.9l-.2 .3 .1 .8 .3 .2h.4l.2 .5-.8 .1-.4-.3v-2.3l-.4-.5zM139.1 135.1h.9v.4h-.9zM139.1 134.4h.9v.4h-.9zM139.1 133.8h.9v.4h-.9zM139.3 137.2h.9v.8h-.9zM132.7 133.6l1.2-1.2 .3-.1 .4-.3 .4 .2h.5l.4 .3 3.1 .1 .2-.1v-.7l-3.2 .2v-1.1h.7l.6 .7h1.9l.8-.7 1.8 1.7 1.1 .1-.4 .4h-1.6l-.6 .6-1.2-.1-.6 .1-.4 .4-.4-.8h-.8l-.3 .1-.1 .9 .5 .4-.4 .5v.6l.3 .4-.4 .5v.7l.4 .4-.3 .4v.6l.4 .4v.3l.4 .4-.1 .1h-1.5l-.8-.7v-.1l.9-.1 .2-.5h-.5v.6h-.2l-.1-.6h-.5l-.1 .3-.5-.4 .1-.1h1.8v-.3l-.3-.3 .4-.4v-.3h-1.4v.3h-.3l-.6-.5h2.3v-.4l-.4-.3 .3-.3v-.3h-1.3v.3l.4 .3-.4 .3v.4h-.9l-1.8-1.8v-.3h.2a.5 .5 0 0 0 .6-.6h1.9l.4 .5-.4 .3v.4h1.3v-.4l-.4-.3 .5-.3v-.4l-3.3 .2-.3-.4h3.6l-.2-.5h-.4v.5h-.2v-.5l-.5 .1-.1 .4h-2.2zM139.2 128h.8v.9h-.8zM141 137.2h.9v.8h-.9zM141.3 133.8h.9v.4h-.9zM141.3 134.4h.9v.4h-.9z"/>
<path d="M141.3 135.1h.9v.4h-.9zM141.8 130.1h1.5v.3h-1.5zM141.8 130.6h1.5v.3h-1.5zM141.8 131.1h1.5v.3h-1.5zM141.8 131.6h1.5v.3h-1.5zM141.8 132.1h1.5v.3h-1.5zM141 128h.8v.9h-.8zM142.6 128h.9v.9h-.9zM140.6 134.2l.5-.4v.7h1.3l.1-.2 .4-.1 1.5-1.4v.4l-1.8 1.8h-.2v-.3l-1.3 .1 .1 .8 1.1 .1 .5-.2 2-1.9 .8-.1 .3-.4h.9v.2h-.7l-.7 .7-.8 .1-.2 .9 .4 .3h.6l.5-.2 1.3 1.3v2.4l-.7 .7h-.5l-.4-.2h-2.3v-.4l.4-.5v-1.3l-1.1-1-1.8-.1-.5-.4 .3-.4zM144.7 132.4h.8v.9h-.8zM144.7 134.2h.8v.9h-.8zM144.5 128h.8v.9h-.8z"/>
<path d="M146.9 126.2h.2l1.2 1.1-.1 3.7-2.6-2.6 .2-.4 .5 .1a.5 .5 0 0 0 .8-.2v-.2a.46 .46 0 0 1 .1-.7zM154.9 133.2h1.9v4.1h-1.9zM154.4 127.2h.8v.9h-.8zM154.4 129.1h.8v.8h-.8zM156.4 127.2h.8v.2l-.8 .1zM156.4 126.7h.8v.2l-.8 .1zM156.4 126.2h.8v.2l-.8 .1zM156.4 125.7h.8v.2l-.8 .1zM156.6 122.1h.8v.8h-.8zM156.6 123.9h.8v.8h-.8zM156.4 131h.9v.8h-.9zM156.4 129.1h1v.8h-1z"/>
<path d="M158.2 123.8h.8v.9h-.8zM158.2 122.1h.8v.9h-.8zM158.6 133.2h1.8v4.1h-1.8zM158.3 125.7h.8v.2l-.8 .1zM158.3 126.2h.8v.2l-.8 .1zM158.3 126.7h.8v.2l-.8 .1zM158.3 127.2h.8v.2l-.8 .1zM158.1 131h1v.8h-1zM158.1 129.1h1v.8h-1zM169.8 139.1h.9v.8h-.9zM170.1 122.2h.8v.9h-.8zM170.1 120.4h.8v.8h-.8z"/>
<path d="M169.9 135.6h.8v1h-.8zM169.9 137.3h.8v1h-.8zM169.5 137.1h1.6l.1 .3-.1 3h-1.8v-3zM171.7 139.1h.8v.8h-.8zM169.2 125.7h3.1v2.5h-3.1zM171.6 135.6h.8v1h-.8zM171.6 137.3h.8v1h-.8zM170 121.8l2.7-.1 .1 .2-.2 .1v1.3l.2 .1v.1l-2.8 .1v-.3h.9l.2-.4h.5l.1 .3 .4 .1-.1-.4h-.4h-.9v.4h-.5v-.9h1.8l.1-.4-.4 .1-.1 .3h-.5l-.1-.3-.3-.1v.4h-.5v-.4zM171.8 120.4h1v.8h-1zM171.8 122.2h1v.8h-1zM173.6 120.4h.9v.8h-.9zM173.6 122.2h.9v.8h-.9z"/>
<path d="M174.7 128.5l.7-.3h3.8a1 1 0 0 1 1 1l-.1 4.7-2.6 2.7-.6 .2-7.3-.1-.3-.4 .1-1 1.4-1.6 .6-.1h3v-4.4zM171.4 137.1h8.2v3.4h-8.2zM177.3 128.2h2.9v5.4h-2.9zM187.4 128.4l.4-.2h1.8l.5 .3 .1 4.7h2.5l.7-.4 5.1 .1 .3 .3v1.6l-.3 .3h-.9a1.12 1.12 0 0 0-1.6-.8l-.6 .8h-7.9l-.2-.5v-5.9zM187.2 128.2h2.9v5.4h-2.9zM192.6 126l.5 .2v.2l-.2 .1v.2h.2l-.2 .5h.2v.2l-.2 .1-.1 1.9-.2-.2zM190.6 131.3l.2-.1h7.8l.2 .1v1l-.2 .1h-5.6l-.4 .2h-1.8l-.3-.2zM193.1 133.7h1.5v.3h-1.5zM193.1 133.2h1.5v.3h-1.5zM193.1 132.7h1.5v.3h-1.5zM193.1 132.2h1.5v.3h-1.5zM193.1 131.7h1.5v.3h-1.5z"/>
<path d="M193.1 131.2h1.5v.3h-1.5zM193.1 130.7h1.5v.3h-1.5zM193.1 130.2h1.5v.3h-1.5zM193.1 129.7h1.5v.3h-1.5zM193.1 129.2h1.5v.3h-1.5zM193.1 128.7h1.5v.3h-1.5zM193.1 128.2h1.5v.3h-1.5zM193.1 127.7h1.5v.3h-1.5zM193.1 127.2h1.5v.3h-1.5zM193.1 126.7h1.5v.3h-1.5zM193.1 126.2h1.5v.3h-1.5zM193.1 125.7h1.5v.3h-1.5z"/>
<path d="M193.1 125.2h1.5v.3h-1.5zM193.1 124.7h1.5v.3h-1.5zM193.1 124.2h1.5v.3h-1.5zM193.1 123.7h1.5v.3h-1.5zM193.1 123.2h1.5v.3h-1.5zM193.1 122.7h1.5v.3h-1.5zM193.1 122.2h1.5v.3h-1.5zM193.1 121.7h1.5v.3h-1.5zM193.1 121.2h1.5v.3h-1.5zM193.1 120.7h1.5v.3h-1.5zM193.1 120.2h1.5v.3h-1.5zM193.2 127.8l2-.2 .2 .2v.3l2.9 .1 .2 .3v.6l-.1 .3-.4 .1h-4.6l-.4-.4v-1z"/>
<path d="M193.1 126.2l6.9-.1v1.8h-3.4v-.5h-3.5zM196.8 133.7h1.5v.3h-1.5zM196.8 133.2h1.5v.3h-1.5zM196.8 132.7h1.5v.3h-1.5zM196.8 132.2h1.5v.3h-1.5zM196.8 131.7h1.5v.3h-1.5zM196.8 131.2h1.5v.3h-1.5zM196.8 130.7h1.5v.3h-1.5zM196.8 130.2h1.5v.3h-1.5zM196.8 129.7h1.5v.3h-1.5zM196.8 129.2h1.5v.3h-1.5zM196.8 128.7h1.5v.3h-1.5z"/>
<path d="M196.8 128.2h1.5v.3h-1.5zM196.8 127.7h1.5v.3h-1.5zM196.8 127.2h1.5v.3h-1.5zM196.8 126.7h1.5v.3h-1.5zM196.8 126.2h1.5v.3h-1.5zM196.8 125.7h1.5v.3h-1.5zM196.8 125.2h1.5v.3h-1.5zM196.8 124.7h1.5v.3h-1.5zM196.8 124.2h1.5v.3h-1.5zM196.8 123.7h1.5v.3h-1.5zM196.8 123.2h1.5v.3h-1.5zM196.8 122.7h1.5v.3h-1.5z"/>
<path d="M196.8 122.2h1.5v.3h-1.5zM196.8 121.7h1.5v.3h-1.5zM196.8 121.2h1.5v.3h-1.5zM196.8 120.7h1.5v.3h-1.5zM196.8 120.2h1.5v.3h-1.5zM198.5 121h.2l2.8 2.8v.2l-.5 .1a.5 .5 0 0 0-.8-.2l-.1 .1h-1.6zM199.2 120.7l3-.1 10.2 10.3-1.3 .1v-.9l-.3-.3h-.8l-.3 .4h-1.1zM210.3 135.1h.8v.8h-.8zM210.3 138.1h.8v.9h-.8zM210 131.9h.9v.8h-.9zM210 130h.9v.9h-.9zM210.3 133.6h.9v.8h-.9z"/>
<path d="M210.3 136.6h.9v.9h-.9zM212.1 135.1h.8v.8h-.8zM212.1 138.1h.8v.9h-.8zM212.8 132.2h1.4v.2h-1.4zM212.8 131.7h1.4v.2h-1.4zM212.8 131.2h1.4v.2h-1.4zM212.8 130.7h1.4v.2h-1.4zM212.8 130.2h1.4v.2h-1.4zM212 133.6h.9v.8h-.9zM212 136.6h.9v.9h-.9zM213.5 134.4l.6-.1 .1 .3h.7l-.1 .2h-.6v.8l.7 .2 .9 .9h1.5l-.1 .3h-.4v.7l-.8 .1-.1 .4-.2-.1v-.5h.9v-.6l-.5 .1-.1 .5h-.3v-.4l-.3-.2-1 .1-.1 1 .2 .2 .5 .1 .2 .2v.4l-.6-.1-.8-.8 .1-1.6-.3-.4zM214.4 135.1h.9v.4h-.9z"/>
<path d="M214.4 134.5h.9v.4h-.9zM214.4 133.8h.9v.4h-.9zM214.5 137.3h.9v.8h-.9zM214.4 128.1h.8v.8h-.8zM216.2 137.3h1v.8h-1zM216.6 133.8h.9v.4h-.9zM216.6 134.5h.9v.4h-.9zM216.6 135.1h.9v.4h-.9zM217.1 130.2h1.4v.2h-1.4zM217.1 130.7h1.4v.2h-1.4zM217.1 131.2h1.4v.2h-1.4zM217.1 131.7h1.4v.2h-1.4z"/>
<path d="M217.1 132.2h1.4v.2h-1.4zM216.2 128.1h.9v.8h-.9zM217.9 128.1h.8v.8h-.8zM216.2 134.2h.1l.1 .4h1.3v-.3l.5-.1 1.3-1.3h.1v.3l-1.8 1.8h-.1v-.2h-1.3v.9h1.1l.6-.2 1.9-1.9 .8-.1 .3-.4 .9 .1v.2h-.7l-.7 .6-.7 .1-.2 .3 .1 .9 .9 .1 .4-.3 1.4 1.5v2.2l-.5 .5-.3-.1a.5 .5 0 0 0-.6-.6l-.4 .3-2.7-.1-.2-.1v-2.3l-.4-.3-1.4 .1-.5-.6 .6-.6zM219.9 132.5h.8v.8h-.8zM219.9 134.3h.8v.8h-.8zM219.7 128.1h.8v.8h-.8zM222.1 126.2h.3l1.1 1.2-.1 3.6-2.6-2.6 .2-.4 .5 .1a.51 .51 0 0 0 .7 0 .51 .51 0 0 0 0-.8l.1-.2a.54 .54 0 0 0-.2-.8zM230.1 133.3h1.9v4.1h-1.9zM229.7 127.3h.8v.8h-.8zM229.7 129.1h.8v.8h-.8zM231.6 122.1h.8v.9h-.8z"/>
<path d="M231.6 124h.8v.8h-.8zM231.6 127.2h.8v.3h-.8zM231.6 126.7h.8v.3h-.8zM231.6 126.2h.8v.3h-.8zM231.6 125.7h.8v.3h-.8zM231.6 131h1v.8h-1zM231.7 129.1h.9v.9h-.9zM233.4 123.9h.8v.9h-.8zM233.4 122.1h.8v1h-.8zM233.8 133.3h1.8v4.1h-1.8zM233.5 125.7h.8v.3h-.8zM233.5 126.2h.8v.3h-.8z"/>
<path d="M233.5 126.7h.8v.3h-.8zM233.5 127.2h.8v.3h-.8zM233.4 131h.9v.8h-.9zM233.4 129.1h.9v.9h-.9z"/>
<circle cx="87.4" cy="79.1" r=".3"/>
<circle cx="90.1" cy="78" r=".3"/>
<circle cx="91.2" cy="78.1" r=".3"/>
<circle cx="91.5" cy="79.6" r=".3"/>
<circle cx="94.2" cy="66.6" r=".3"/>
<circle cx="94.9" cy="78.8" r=".3"/>
<circle cx="95.9" cy="73.4" r=".65"/>
<circle cx="95.9" cy="70.9" r=".65"/>
<circle cx="95.9" cy="76" r=".65"/>
<circle cx="97.8" cy="72.3" r=".3"/>
<circle cx="99.6" cy="71.7" r=".3"/>
<circle cx="99.8" cy="74.9" r=".3"/>
<circle cx="99.8" cy="77.2" r=".3"/>
<circle cx="99.9" cy="73.4" r=".3"/>
<circle cx="100.5" cy="79.5" r=".3"/>
<circle cx="100.5" cy="67.9" r=".3"/>
<circle cx="100.5" cy="69.9" r=".3"/>
<circle cx="100.6" cy="78.6" r=".3"/>
<circle cx="103.8" cy="67.7" r=".3"/>
<circle cx="105.6" cy="67.4" r=".3"/>
<circle cx="106.6" cy="67.7" r=".3"/>
<circle cx="109.2" cy="66.6" r=".3"/>
<circle cx="112.6" cy="69.2" r=".3"/>
<circle cx="112.6" cy="68.4" r=".3"/>
<circle cx="113.1" cy="74.5" r=".3"/>
<circle cx="113.3" cy="73.2" r=".3"/>
<circle cx="113.7" cy="77.5" r=".3"/>
<circle cx="113.9" cy="71.1" r=".3"/>
<circle cx="114.8" cy="72" r=".3"/>
<circle cx="116.1" cy="79.7" r=".3"/>
<circle cx="117.9" cy="68.7" r=".35"/>
<circle cx="118.4" cy="69.9" r=".35"/>
<circle cx="118.4" cy="67.6" r=".35"/>
<circle cx="119.4" cy="73.9" r=".3"/>
<circle cx="119.5" cy="67.1" r=".35"/>
<circle cx="119.5" cy="68.7" r="2.2"/>
<circle cx="119.5" cy="70.4" r=".35"/>
<circle cx="120.7" cy="69.9" r=".35"/>
<circle cx="120.7" cy="67.6" r=".35"/>
<circle cx="121" cy="78.7" r=".3"/>
<circle cx="121" cy="77.2" r=".3"/>
<circle cx="121.2" cy="68.7" r=".35"/>
<circle cx="126" cy="77.8" r=".3"/>
<circle cx="126.1" cy="77.1" r=".3"/>
<circle cx="126.7" cy="77.8" r=".3"/>
<circle cx="126.8" cy="77.1" r=".3"/>
<circle cx="127.3" cy="77.8" r=".3"/>
<circle cx="127.5" cy="77.1" r=".3"/>
<circle cx="127.5" cy="78.4" r=".3"/>
<circle cx="130.1" cy="74.9" r=".3"/>
<circle cx="130.1" cy="74.2" r=".3"/>
<circle cx="130.8" cy="74.9" r=".3"/>
<circle cx="130.8" cy="74.2" r=".3"/>
<circle cx="131.5" cy="74.9" r=".3"/>
<circle cx="131.5" cy="74.2" r=".3"/>
<circle cx="145.7" cy="67" r=".5"/>
<circle cx="145.7" cy="68.2" r=".5"/>
<circle cx="146.8" cy="67" r=".5"/>
<circle cx="146.8" cy="68.2" r=".5"/>
<circle cx="148" cy="67.1" r=".5"/>
<circle cx="148" cy="68.2" r=".5"/>
<circle cx="163.4" cy="79.1" r=".3"/>
<circle cx="165.7" cy="78.1" r=".3"/>
<circle cx="167.3" cy="78" r=".3"/>
<circle cx="167.4" cy="79.3" r=".3"/>
<circle cx="170.9" cy="78.8" r=".3"/>
<circle cx="172" cy="70.8" r=".65"/>
<circle cx="172" cy="75.9" r=".65"/>
<circle cx="172" cy="73.4" r=".65"/>
<circle cx="175.7" cy="71.7" r=".3"/>
<circle cx="175.8" cy="74.9" r=".3"/>
<circle cx="175.8" cy="77.2" r=".3"/>
<circle cx="176" cy="73.3" r=".3"/>
<circle cx="176.5" cy="79.5" r=".3"/>
<circle cx="176.5" cy="67.9" r=".3"/>
<circle cx="176.6" cy="69.9" r=".3"/>
<circle cx="176.6" cy="78.6" r=".3"/>
<circle cx="180.8" cy="67.2" r=".3"/>
<circle cx="181.9" cy="67.7" r=".3"/>
<circle cx="183.7" cy="67.5" r=".3"/>
<circle cx="185.2" cy="66.6" r=".3"/>
<circle cx="188.5" cy="79.8" r=".3"/>
<circle cx="188.6" cy="69.2" r=".3"/>
<circle cx="188.7" cy="68.4" r=".3"/>
<circle cx="189.2" cy="74.5" r=".3"/>
<circle cx="189.8" cy="77.5" r=".3"/>
<circle cx="189.9" cy="71.1" r=".3"/>
<circle cx="190.8" cy="72" r=".3"/>
<circle cx="192.2" cy="79.6" r=".3"/>
<circle cx="194" cy="68.7" r=".35"/>
<circle cx="194.5" cy="69.9" r=".35"/>
<circle cx="194.5" cy="67.6" r=".35"/>
<circle cx="195.6" cy="68.7" r="2.2"/>
<circle cx="195.6" cy="67.1" r=".35"/>
<circle cx="195.6" cy="70.4" r=".35"/>
<circle cx="195.9" cy="74.3" r=".3"/>
<circle cx="196.8" cy="69.9" r=".35"/>
<circle cx="196.8" cy="67.6" r=".35"/>
<circle cx="197.3" cy="68.7" r=".35"/>
<circle cx="197.6" cy="78.5" r=".3"/>
<circle cx="197.6" cy="77.1" r=".3"/>
<circle cx="197.6" cy="79.9" r=".3"/>
<circle cx="202.1" cy="77.8" r=".3"/>
<circle cx="202.2" cy="77.1" r=".3"/>
<circle cx="202.7" cy="77.8" r=".3"/>
<circle cx="202.9" cy="77.1" r=".3"/>
<circle cx="203.4" cy="77.8" r=".3"/>
<circle cx="203.4" cy="78.4" r=".3"/>
<circle cx="203.5" cy="77.1" r=".3"/>
<circle cx="206.1" cy="74.9" r=".3"/>
<circle cx="206.1" cy="74.2" r=".3"/>
<circle cx="206.9" cy="74.9" r=".3"/>
<circle cx="206.9" cy="74.2" r=".3"/>
<circle cx="207.6" cy="74.9" r=".3"/>
<circle cx="207.6" cy="74.2" r=".3"/>
<circle cx="222.6" cy="67" r=".5"/>
<circle cx="222.7" cy="68.2" r=".5"/>
<circle cx="223.8" cy="67" r=".5"/>
<circle cx="223.8" cy="68.2" r=".5"/>
<circle cx="224.9" cy="68.2" r=".5"/>
<circle cx="224.9" cy="67" r=".5"/>
<circle cx="91.3" cy="82.1" r=".3"/>
<circle cx="93.2" cy="81.8" r="1"/>
<circle cx="94.2" cy="80.2" r=".3"/>
<circle cx="100.2" cy="99.2" r="1.4"/>
<circle cx="100.2" cy="86.7" r="1.45"/>
<circle cx="102.3" cy="85.2" r=".76"/>
<circle cx="102.3" cy="88.2" r=".76"/>
<circle cx="103" cy="83.9" r=".4"/>
<circle cx="104.4" cy="82.9" r=".4"/>
<circle cx="105.3" cy="85.2" r=".76"/>
<circle cx="105.3" cy="88.2" r=".76"/>
<circle cx="105.7" cy="99.2" r="1.4"/>
<circle cx="105.8" cy="82.7" r=".4"/>
<circle cx="106.6" cy="92.8" r=".4"/>
<circle cx="106.7" cy="83.8" r=".4"/>
<circle cx="107.3" cy="91.2" r=".4"/>
<circle cx="107.3" cy="94.4" r=".4"/>
<circle cx="107.7" cy="82.5" r=".4"/>
<circle cx="108.3" cy="85.2" r=".76"/>
<circle cx="108.3" cy="88.2" r=".76"/>
<circle cx="108.8" cy="92.8" r="3"/>
<circle cx="108.8" cy="95" r=".4"/>
<circle cx="108.8" cy="90.5" r=".4"/>
<circle cx="110.4" cy="91.2" r=".4"/>
<circle cx="110.4" cy="94.4" r=".4"/>
<circle cx="110.5" cy="86.7" r="1.45"/>
<circle cx="111.1" cy="92.8" r=".4"/>
<circle cx="113.4" cy="84" r=".3"/>
<circle cx="117.1" cy="86.6" r=".3"/>
<circle cx="117.1" cy="85.5" r=".3"/>
<circle cx="117.9" cy="87.4" r=".3"/>
<circle cx="118.4" cy="94.3" r=".3"/>
<circle cx="118.4" cy="85.6" r=".3"/>
<circle cx="118.8" cy="87.5" r=".3"/>
<circle cx="119.3" cy="93.9" r=".3"/>
<circle cx="119.3" cy="80.5" r=".3"/>
<circle cx="119.5" cy="86.2" r=".3"/>
<circle cx="119.8" cy="83.8" r=".3"/>
<circle cx="120.2" cy="81.4" r=".3"/>
<circle cx="120.8" cy="82" r=".3"/>
<circle cx="120.9" cy="80.1" r=".3"/>
<circle cx="121.8" cy="82.1" r=".3"/>
<circle cx="121.8" cy="82.9" r=".3"/>
<circle cx="122" cy="88.2" r=".3"/>
<circle cx="126.6" cy="88.9" r=".3"/>
<circle cx="126.9" cy="87.6" r=".3"/>
<circle cx="127.2" cy="88.5" r=".3"/>
<circle cx="137.6" cy="81.5" r=".3"/>
<circle cx="149.6" cy="97.6" r=".3"/>
<circle cx="149.7" cy="95.9" r=".3"/>
<circle cx="152.2" cy="95.9" r=".3"/>
<circle cx="152.2" cy="93.3" r=".3"/>
<circle cx="152.2" cy="91.8" r=".3"/>
<circle cx="152.5" cy="99.4" r=".3"/>
<circle cx="154.4" cy="85.7" r=".5"/>
<circle cx="154.4" cy="83" r=".5"/>
<circle cx="154.4" cy="84.3" r=".5"/>
<circle cx="154.7" cy="92.8" r=".3"/>
<circle cx="154.9" cy="90.8" r=".3"/>
<circle cx="157.4" cy="92.4" r=".3"/>
<circle cx="157.4" cy="97.4" r=".3"/>
<circle cx="160" cy="89.5" r=".3"/>
<circle cx="165.3" cy="90.3" r=".3"/>
<circle cx="165.3" cy="89.6" r=".3"/>
<circle cx="166" cy="90.3" r=".3"/>
<circle cx="166" cy="89.6" r=".3"/>
<circle cx="166.7" cy="90.3" r=".3"/>
<circle cx="166.7" cy="89.6" r=".3"/>
<circle cx="167.4" cy="90.3" r=".3"/>
<circle cx="167.4" cy="89.6" r=".3"/>
<circle cx="167.6" cy="81.2" r=".3"/>
<circle cx="168.1" cy="90.3" r=".3"/>
<circle cx="168.1" cy="89.6" r=".3"/>
<circle cx="169.8" cy="82" r="1"/>
<circle cx="170.2" cy="80.1" r=".3"/>
<circle cx="176.1" cy="86.7" r="1.46"/>
<circle cx="178.3" cy="85.2" r=".76"/>
<circle cx="178.3" cy="88.2" r=".76"/>
<circle cx="181.3" cy="85.2" r=".76"/>
<circle cx="181.3" cy="88.2" r=".76"/>
<circle cx="182.7" cy="92.8" r=".4"/>
<circle cx="183.4" cy="91.2" r=".4"/>
<circle cx="183.4" cy="94.4" r=".4"/>
<circle cx="184.3" cy="85.2" r=".76"/>
<circle cx="184.3" cy="88.2" r=".76"/>
<circle cx="184.9" cy="92.8" r="3"/>
<circle cx="184.9" cy="95" r=".4"/>
<circle cx="184.9" cy="90.5" r=".4"/>
<circle cx="185.8" cy="83.2" r=".3"/>
<circle cx="186.4" cy="86.7" r="1.46"/>
<circle cx="186.5" cy="91.2" r=".4"/>
<circle cx="186.5" cy="94.4" r=".4"/>
<circle cx="187.2" cy="92.8" r=".4"/>
<circle cx="188.9" cy="83.9" r=".3"/>
<circle cx="193.1" cy="85.5" r=".3"/>
<circle cx="193.1" cy="86.6" r=".3"/>
<circle cx="193.7" cy="87.5" r=".3"/>
<circle cx="194.3" cy="85" r=".3"/>
<circle cx="194.5" cy="93.7" r=".3"/>
<circle cx="194.5" cy="87.5" r=".3"/>
<circle cx="195" cy="86" r=".3"/>
<circle cx="195.4" cy="80.5" r=".3"/>
<circle cx="195.4" cy="82.8" r=".3"/>
<circle cx="196.3" cy="81.3" r=".3"/>
<circle cx="196.8" cy="81.9" r=".3"/>
<circle cx="197.9" cy="82.1" r=".3"/>
<circle cx="198.1" cy="88.2" r=".3"/>
<circle cx="198.1" cy="85.3" r=".3"/>
<circle cx="199.2" cy="91.1" r=".3"/>
<circle cx="199.5" cy="84.4" r=".3"/>
<circle cx="202.4" cy="88.6" r=".3"/>
<circle cx="202.9" cy="87.4" r=".3"/>
<circle cx="203.2" cy="88.5" r=".3"/>
<circle cx="213.7" cy="81.5" r=".3"/>
<circle cx="217" cy="86.4" r=".3"/>
<circle cx="225.5" cy="96.2" r=".3"/>
<circle cx="225.7" cy="99.1" r=".3"/>
<circle cx="228.3" cy="98.1" r=".3"/>
<circle cx="230.2" cy="99.7" r=".3"/>
<circle cx="230.2" cy="85.2" r=".5"/>
<circle cx="230.2" cy="86.8" r=".5"/>
<circle cx="230.3" cy="83.6" r=".5"/>
<circle cx="230.8" cy="93.1" r=".3"/>
<circle cx="230.8" cy="94.5" r=".3"/>
<circle cx="230.8" cy="91.7" r=".3"/>
<circle cx="231.5" cy="83" r=".5"/>
<circle cx="233.1" cy="83" r=".5"/>
<circle cx="233.3" cy="93.1" r=".3"/>
<circle cx="233.4" cy="98" r=".3"/>
<circle cx="236.5" cy="94.3" r=".3"/>
<circle cx="90" cy="112.1" r=".3"/>
<circle cx="91.4" cy="111.5" r=".3"/>
<circle cx="94.8" cy="119.6" r=".5"/>
<circle cx="95.2" cy="114.5" r=".3"/>
<circle cx="96" cy="119.6" r=".5"/>
<circle cx="97.1" cy="119.6" r=".5"/>
<circle cx="97.3" cy="111.2" r=".3"/>
<circle cx="97.4" cy="113.7" r=".3"/>
<circle cx="97.5" cy="112.7" r=".3"/>
<circle cx="100.1" cy="113.1" r=".3"/>
<circle cx="100.3" cy="115.3" r=".3"/>
<circle cx="101" cy="109.4" r=".4"/>
<circle cx="102.8" cy="105.8" r=".3"/>
<circle cx="103.9" cy="107.6" r=".3"/>
<circle cx="106.9" cy="108.3" r=".3"/>
<circle cx="107.5" cy="105.1" r=".3"/>
<circle cx="109.5" cy="117.4" r=".3"/>
<circle cx="115" cy="112.1" r=".3"/>
<circle cx="116.6" cy="112.7" r=".3"/>
<circle cx="117.2" cy="116.1" r=".3"/>
<circle cx="117.2" cy="117.8" r=".3"/>
<circle cx="117.2" cy="116.9" r=".3"/>
<circle cx="120" cy="112.8" r=".3"/>
<circle cx="122.9" cy="112.6" r=".3"/>
<circle cx="123.3" cy="110.3" r=".3"/>
<circle cx="124" cy="111.1" r=".3"/>
<circle cx="127.8" cy="112.9" r=".3"/>
<circle cx="128.5" cy="118.8" r=".3"/>
<circle cx="129.5" cy="118.8" r=".3"/>
<circle cx="130.1" cy="119.7" r=".3"/>
<circle cx="136.1" cy="112.5" r=".4"/>
<circle cx="136.8" cy="119.6" r="1.45"/>
<circle cx="136.8" cy="110.9" r=".4"/>
<circle cx="136.8" cy="114.1" r=".4"/>
<circle cx="138.4" cy="112.5" r="3"/>
<circle cx="138.4" cy="114.7" r=".4"/>
<circle cx="138.4" cy="110.2" r=".4"/>
<circle cx="138.9" cy="118.1" r=".76"/>
<circle cx="140" cy="110.9" r=".4"/>
<circle cx="140" cy="114.1" r=".4"/>
<circle cx="140.6" cy="112.5" r=".4"/>
<circle cx="141.9" cy="118.1" r=".76"/>
<circle cx="144.9" cy="118.1" r=".76"/>
<circle cx="145.9" cy="114.8" r=".3"/>
<circle cx="146.4" cy="115.5" r=".4"/>
<circle cx="147.1" cy="119.6" r="1.46"/>
<circle cx="155" cy="117.4" r=".3"/>
<circle cx="155" cy="116.6" r=".3"/>
<circle cx="155.7" cy="117.4" r=".3"/>
<circle cx="155.7" cy="116.6" r=".3"/>
<circle cx="156.5" cy="117.4" r=".3"/>
<circle cx="156.5" cy="116.6" r=".3"/>
<circle cx="157.2" cy="117.4" r=".3"/>
<circle cx="157.2" cy="116.6" r=".3"/>
<circle cx="157.8" cy="117.4" r=".3"/>
<circle cx="157.8" cy="116.6" r=".3"/>
<circle cx="160.2" cy="112.9" r=".3"/>
<circle cx="165.1" cy="108.2" r=".3"/>
<circle cx="165.2" cy="110.1" r=".4"/>
<circle cx="166.6" cy="111.5" r=".3"/>
<circle cx="167.6" cy="119.4" r=".5"/>
<circle cx="168.8" cy="119.4" r=".5"/>
<circle cx="170.4" cy="114.6" r=".3"/>
<circle cx="172.5" cy="111.2" r=".3"/>
<circle cx="172.6" cy="113.7" r=".3"/>
<circle cx="172.7" cy="112.8" r=".3"/>
<circle cx="175.3" cy="113.1" r=".3"/>
<circle cx="175.5" cy="115.4" r=".3"/>
<circle cx="176.3" cy="107.6" r=".3"/>
<circle cx="180.5" cy="111" r=".4"/>
<circle cx="184.4" cy="109.5" r=".4"/>
<circle cx="184.7" cy="117.4" r=".3"/>
<circle cx="184.7" cy="110.6" r=".3"/>
<circle cx="188.6" cy="109.5" r=".3"/>
<circle cx="190.1" cy="109.2" r=".3"/>
<circle cx="190.7" cy="111.6" r=".3"/>
<circle cx="191.7" cy="108.5" r=".3"/>
<circle cx="191.9" cy="112.7" r=".3"/>
<circle cx="192.4" cy="117.8" r=".3"/>
<circle cx="192.6" cy="116.4" r=".3"/>
<circle cx="192.7" cy="110.4" r=".3"/>
<circle cx="195.2" cy="112.8" r=".3"/>
<circle cx="198.1" cy="112.6" r=".3"/>
<circle cx="198.9" cy="115" r=".3"/>
<circle cx="203" cy="118.1" r=".3"/>
<circle cx="203" cy="113" r=".3"/>
<circle cx="203.7" cy="118.8" r=".3"/>
<circle cx="204.7" cy="118.9" r=".3"/>
<circle cx="205.3" cy="119.8" r=".3"/>
<circle cx="211.3" cy="112.6" r=".4"/>
<circle cx="212" cy="114.2" r=".4"/>
<circle cx="212" cy="111" r=".4"/>
<circle cx="212" cy="119.7" r="1.45"/>
<circle cx="213.5" cy="112.6" r="3"/>
<circle cx="213.5" cy="110.3" r=".4"/>
<circle cx="213.5" cy="114.8" r=".4"/>
<circle cx="214.1" cy="118.2" r=".76"/>
<circle cx="215.1" cy="114.2" r=".4"/>
<circle cx="215.1" cy="111" r=".4"/>
<circle cx="215.8" cy="112.6" r=".4"/>
<circle cx="217.1" cy="118.2" r=".76"/>
<circle cx="218.7" cy="119.6" r=".3"/>
<circle cx="220.1" cy="118.2" r=".76"/>
<circle cx="222.3" cy="119.7" r="1.46"/>
<circle cx="223" cy="109.4" r="1.27"/>
<circle cx="223" cy="104.4" r="1.28"/>
<circle cx="227.2" cy="117.2" r=".3"/>
<circle cx="227.2" cy="116.4" r=".3"/>
<circle cx="227.9" cy="117.2" r=".3"/>
<circle cx="227.9" cy="116.4" r=".3"/>
<circle cx="228.6" cy="117.2" r=".3"/>
<circle cx="228.6" cy="116.4" r=".3"/>
<circle cx="229.3" cy="117.2" r=".3"/>
<circle cx="229.3" cy="116.4" r=".3"/>
<circle cx="230" cy="117.2" r=".3"/>
<circle cx="230" cy="116.4" r=".3"/>
<circle cx="233" cy="101.4" r=".75"/>
<circle cx="233" cy="112.4" r=".75"/>
<circle cx="109.5" cy="124.8" r=".3"/>
<circle cx="115.6" cy="132.1" r=".3"/>
<circle cx="115.6" cy="131.4" r=".3"/>
<circle cx="116.3" cy="132.1" r=".3"/>
<circle cx="116.3" cy="131.4" r=".3"/>
<circle cx="116.8" cy="122.3" r=".3"/>
<circle cx="116.9" cy="121.5" r=".3"/>
<circle cx="116.9" cy="120.7" r=".3"/>
<circle cx="117.1" cy="132.1" r=".3"/>
<circle cx="117.1" cy="131.4" r=".3"/>
<circle cx="119.7" cy="129.2" r=".3"/>
<circle cx="119.8" cy="127.9" r=".3"/>
<circle cx="119.8" cy="128.5" r=".3"/>
<circle cx="120.3" cy="129.2" r=".3"/>
<circle cx="120.5" cy="128.5" r=".3"/>
<circle cx="121" cy="129.2" r=".3"/>
<circle cx="121.1" cy="128.5" r=".3"/>
<circle cx="123.6" cy="128.4" r=".3"/>
<circle cx="123.6" cy="129.1" r=".3"/>
<circle cx="123.8" cy="126.1" r=".3"/>
<circle cx="123.8" cy="126.8" r=".3"/>
<circle cx="124.3" cy="128.7" r=".3"/>
<circle cx="124.4" cy="126.5" r=".3"/>
<circle cx="125.1" cy="121" r=".3"/>
<circle cx="125.1" cy="126.1" r=".3"/>
<circle cx="125.1" cy="126.8" r=".3"/>
<circle cx="125.3" cy="124.2" r=".3"/>
<circle cx="125.3" cy="123.4" r=".3"/>
<circle cx="125.7" cy="137.7" r=".35"/>
<circle cx="126.2" cy="138.9" r=".35"/>
<circle cx="126.2" cy="136.6" r=".35"/>
<circle cx="126.4" cy="124.4" r=".3"/>
<circle cx="126.9" cy="125" r=".3"/>
<circle cx="127.4" cy="137.7" r="2.2"/>
<circle cx="127.4" cy="136.1" r=".35"/>
<circle cx="127.4" cy="139.4" r=".35"/>
<circle cx="127.5" cy="133.6" r=".3"/>
<circle cx="127.6" cy="120.1" r=".3"/>
<circle cx="127.8" cy="123.5" r=".3"/>
<circle cx="127.8" cy="125.8" r=".3"/>
<circle cx="128.6" cy="138.9" r=".35"/>
<circle cx="128.6" cy="136.6" r=".35"/>
<circle cx="128.8" cy="120.7" r=".3"/>
<circle cx="129" cy="137.7" r=".35"/>
<circle cx="130.1" cy="120.8" r=".3"/>
<circle cx="131" cy="126.7" r=".3"/>
<circle cx="132.4" cy="134.3" r=".3"/>
<circle cx="133.3" cy="135.2" r=".3"/>
<circle cx="133.9" cy="129.1" r=".3"/>
<circle cx="134" cy="131.8" r=".3"/>
<circle cx="134.3" cy="122.4" r=".3"/>
<circle cx="134.5" cy="137.9" r=".3"/>
<circle cx="134.6" cy="137.1" r=".3"/>
<circle cx="137.1" cy="123.2" r=".3"/>
<circle cx="138" cy="139.7" r=".3"/>
<circle cx="138.9" cy="121.1" r=".76"/>
<circle cx="140.5" cy="138.6" r=".3"/>
<circle cx="141.6" cy="138.9" r=".3"/>
<circle cx="141.9" cy="121.1" r=".76"/>
<circle cx="142.8" cy="139" r=".3"/>
<circle cx="142.8" cy="137.7" r=".3"/>
<circle cx="144" cy="138.4" r=".3"/>
<circle cx="144.9" cy="121.1" r=".76"/>
<circle cx="146.6" cy="127.7" r=".3"/>
<circle cx="146.6" cy="136.5" r=".3"/>
<circle cx="146.7" cy="126.8" r=".3"/>
<circle cx="147.3" cy="133" r=".3"/>
<circle cx="147.4" cy="131.4" r=".3"/>
<circle cx="147.4" cy="128.2" r=".3"/>
<circle cx="147.5" cy="134.6" r=".3"/>
<circle cx="151.3" cy="130.4" r=".65"/>
<circle cx="151.3" cy="132.9" r=".65"/>
<circle cx="151.3" cy="135.5" r=".65"/>
<circle cx="152.3" cy="127.5" r=".3"/>
<circle cx="152.6" cy="126.7" r=".3"/>
<circle cx="153.6" cy="124.5" r="1"/>
<circle cx="154.8" cy="128.5" r=".3"/>
<circle cx="155.8" cy="124.2" r=".3"/>
<circle cx="156" cy="126.9" r=".3"/>
<circle cx="157.1" cy="128.5" r=".3"/>
<circle cx="159.8" cy="127.2" r=".3"/>
<circle cx="168.8" cy="121.7" r=".5"/>
<circle cx="168.8" cy="120.5" r=".5"/>
<circle cx="174.4" cy="138.2" r=".5"/>
<circle cx="174.4" cy="139.3" r=".5"/>
<circle cx="175.5" cy="138.2" r=".5"/>
<circle cx="175.5" cy="139.4" r=".5"/>
<circle cx="184.7" cy="124.9" r=".3"/>
<circle cx="190.9" cy="132.2" r=".3"/>
<circle cx="190.9" cy="131.5" r=".3"/>
<circle cx="191.6" cy="132.2" r=".3"/>
<circle cx="191.6" cy="131.5" r=".3"/>
<circle cx="192" cy="122.6" r=".3"/>
<circle cx="192" cy="121.8" r=".3"/>
<circle cx="192.3" cy="132.2" r=".3"/>
<circle cx="192.3" cy="131.5" r=".3"/>
<circle cx="194.9" cy="129.2" r=".3"/>
<circle cx="195" cy="127.9" r=".3"/>
<circle cx="195.1" cy="128.6" r=".3"/>
<circle cx="195.6" cy="129.2" r=".3"/>
<circle cx="195.7" cy="128.6" r=".3"/>
<circle cx="196.3" cy="129.2" r=".3"/>
<circle cx="196.4" cy="128.6" r=".3"/>
<circle cx="198.9" cy="127.7" r=".3"/>
<circle cx="198.9" cy="126.3" r=".3"/>
<circle cx="198.9" cy="127" r=".3"/>
<circle cx="199.4" cy="123" r=".3"/>
<circle cx="199.5" cy="127.4" r=".3"/>
<circle cx="199.5" cy="126.7" r=".3"/>
<circle cx="200.3" cy="121.1" r=".3"/>
<circle cx="200.6" cy="124.3" r=".3"/>
<circle cx="200.9" cy="137.7" r=".35"/>
<circle cx="201.4" cy="138.9" r=".35"/>
<circle cx="201.4" cy="136.6" r=".35"/>
<circle cx="201.6" cy="124.4" r=".3"/>
<circle cx="202.2" cy="125" r=".3"/>
<circle cx="202.5" cy="132.1" r=".3"/>
<circle cx="202.5" cy="137.7" r="2.2"/>
<circle cx="202.5" cy="136.1" r=".35"/>
<circle cx="202.5" cy="139.4" r=".35"/>
<circle cx="202.9" cy="120.2" r=".3"/>
<circle cx="203" cy="123.6" r=".3"/>
<circle cx="203" cy="125.9" r=".3"/>
<circle cx="203.7" cy="138.9" r=".35"/>
<circle cx="203.7" cy="136.6" r=".35"/>
<circle cx="204" cy="120.8" r=".3"/>
<circle cx="204.2" cy="137.7" r=".35"/>
<circle cx="205.3" cy="120.8" r=".3"/>
<circle cx="206.3" cy="126.7" r=".3"/>
<circle cx="207.6" cy="134.3" r=".3"/>
<circle cx="208.3" cy="131" r=".3"/>
<circle cx="208.5" cy="135.3" r=".3"/>
<circle cx="208.6" cy="128.8" r=".3"/>
<circle cx="208.9" cy="133.3" r=".3"/>
<circle cx="209.3" cy="131.9" r=".3"/>
<circle cx="209.5" cy="122.4" r=".3"/>
<circle cx="209.8" cy="138" r=".3"/>
<circle cx="209.8" cy="137.1" r=".3"/>
<circle cx="212.5" cy="123" r=".3"/>
<circle cx="212.8" cy="139.6" r=".3"/>
<circle cx="214.1" cy="121.2" r=".76"/>
<circle cx="215.7" cy="138.7" r=".3"/>
<circle cx="216.6" cy="123.8" r=".3"/>
<circle cx="217" cy="138.8" r=".3"/>
<circle cx="217.1" cy="121.2" r=".76"/>
<circle cx="220.1" cy="121.2" r=".76"/>
<circle cx="221.2" cy="139.1" r=".3"/>
<circle cx="221.8" cy="127.7" r=".3"/>
<circle cx="221.8" cy="136.5" r=".3"/>
<circle cx="221.9" cy="126.8" r=".3"/>
<circle cx="222" cy="138.2" r=".3"/>
<circle cx="222.5" cy="133" r=".3"/>
<circle cx="222.6" cy="131.5" r=".3"/>
<circle cx="222.7" cy="129.2" r=".3"/>
<circle cx="222.7" cy="134.7" r=".3"/>
<circle cx="226.5" cy="139.3" r=".3"/>
<circle cx="226.5" cy="135.5" r=".65"/>
<circle cx="226.5" cy="130.4" r=".65"/>
<circle cx="226.5" cy="133" r=".65"/>
<circle cx="227.5" cy="127.5" r=".3"/>
<circle cx="228.3" cy="126.3" r=".3"/>
<circle cx="229.5" cy="124.5" r="1"/>
<circle cx="230.4" cy="131.3" r=".4"/>
<circle cx="230.9" cy="126.7" r=".3"/>
<circle cx="231.1" cy="127.8" r=".3"/>
<circle cx="233" cy="128.4" r=".3"/>
<circle cx="235" cy="127.2" r=".3"/>
<circle cx="236" cy="128.1" r=".3"/>
</g>
<path d="M151.3 75.2h.6M156.8 75.2h.6M156.8 79.4h.6M227.4 75.2h.6M232.9 75.2h.6M232.9 79.4h.6M89.7 130.1h.6M89.7 125.9h.6M95.2 130.1h.6M165 131.1h.6M165 126.9h.6M170.5 131.1h.6" fill="none" stroke="#000" stroke-width="2.7"/>
<path d="M114.8 89.1h.7M117.4 91.2h1.1M120.4 89.1h.7M190.8 89h.7M193.4 91.2h1.1M196.4 89h.7M126.1 117.3h.7M128.7 115.1h1.1M131.7 117.3h.7M201.3 117.3h.7M203.9 115.2h1.1M206.9 117.3h.7" fill="none" stroke="#000" stroke-width="1.1"/>
<g fill="none" stroke="#000" stroke-width=".21">
<path d="M87.4 79.1l.3 .4h.8M88.5 76.8l1.2 1.2h.4M90.4 79.5l1.1 .1M92.3 78.7l-.6-.6h-.5l-.8 .9M94.9 78.8v3.5l-1.3 1.2h-1.9l-1.5-1.5M95.9 73.4l1.1-1.1v-3l3.1-3.1h8.6l.2-.2h.5l.2 .2h2.2l7.6 7.7M99.8 74.9l.6 .7h4.2M101.3 66.6h.1M101.5 66.2h.1M103.8 67.7v1l1.4 1.3h1.3l1.1 1h-.6l-.2 .3v1.1l-.9 1h-1.8l-.7 .7v.5l.5 .5h.7M104.1 77.9h1.6M104.6 76.1l-.5 .5v2.4l-.5 .5h-3.1"/>
<path d="M105.4 72.3h-1l-2 2.1h-2.9l-.3 .3v.4l2.7 2.8h.4l-.8 .7h-.9M105.4 71h-.9l-2.4 2.5h-2.1l-.1-.1M105.6 67.4l.2-.2h2.3l.6 .6v2.3l.4 .4v1.4l-.5 .4h-1M108.9 74.1l.4-.4h2.3l.3 .4M108.9 75.6h.8l10.4 10.4h4.8M109.2 66.6h.3l.4 .4v2.3M109.9 72.4v-1.5l-.9-.9v-2.4l-1-1h-7.5l-.9 .8v2.6l1.7 1.7h.8l-1.1 1h-1.8v.9l-.6 .6v4.9l1.3 1.3h4.5l2.1-2v-2.8l-1.1-1.1-.8 .1M111.9 75.9h2l9.7 9.7h1.1M112.6 68.4l2.8 2.8v1.9l-2 2h-5.5l-.3 .4v2.4h-.2l-.5-.6v-1.7l-1.5-1.5h-.8M114.8 72v.8l-1.7 1.7M163.4 79.1l.4 .4h.7M164.6 76.8h.2l.9 1v.3"/>
<path d="M166.4 80l-.9 .1v.9l-.9 1v.1M166.4 79h.1M167.4 79.3l-.1 .2h-.9M168.4 78.6l-.6-.6h-.5l-.9 1M170.9 78.8l.5 .5v3.2l-.9 1h-1.6l-1.3-1.4h-1.2M172 73.4l1.1-1.1v-3l3.3-3.3h11.2l8.3 8.3 4.1-4.1h14.2l2.8 2.8v13.4M175.8 74.9l.7 .7h4.2M176.6 69.9h4.9l.6 .6v1l-.1 .2h-.6M180.2 77.9l-1.7 1.6h-2M180.2 77.9h1.6M180.7 76.1l-.5 .4v1.4M180.8 67.2l.1 1.9 .3 .3h.7l1.6 1.6"/>
<path d="M181.4 72.3h-.9l-2.1 2h-2.8l-.4 .4v.4l2.8 2.8h.3l-.7 .7h-1M181.4 71h-.8l-2.5 2.5h-2l-.1-.2M181.7 68.7l1.5 1.4h.7l.4 .4v1l-.1 .2h-1.1l-.2 .1v1.5l1.3 1.3h.8M181.7 68.7h.1M181.9 67.7l.9-.9h1l1 1.1v3.8l-.6 .6h-.6M183.6 71h-.4l-.6 .7v.8l-.4 .4h-1.6l-1.2 1.2v.4l.5 .6h.8M185 74.1h.7l.3 .2h1.7l.3 .3M185 75.6h.7l10.5 10.4h4.7M185.2 66.6h.4l.3 .3 .1 2.4M186 72.4l-.1-1.9-.7-.8v-2.2l-1.1-1.1h-7l-1.4 1.5v2l1.7 1.7h.7l-1.1 1.1h-1.7v.9l-.6 .6v4.9l1.3 1.3h4.5l2-2v-2.8l-1.1-1.1-.7 .1M188 76.4h2.5l9.1 9.2h1.2M188.7 68.4l2.7 2.8v1.8l-2.4 2.5h-2.8l-.4-.4h-1.8l-.4 .3v2.5h-.1l-.6-.6v-1.8l-1.4-1.4h-.8"/>
<path d="M190.8 72v.8l-1.6 1.7M90.2 82h.1M94.2 80.2v.7l-1 .9M105.8 82.7l-1.2 1.2h-1.6M106.7 83.8h-1.4l-1.4 1.4v.4l-1.6 1.6v1M107.7 82.5l-.4 .4v4.3l1 1M113.4 84v.5l2.1 2.1h1.6v1.1l.4 .4 4.2-.1 .3 .2M117.1 85.5l1.3 .1M118.4 94.3l-.3 .3v1M118.8 87.5h.1M118.8 87.5h6.1M119.3 93.9l-.2 .2v1.5"/>
<path d="M119.3 80.5l.4 .3h4l.2-.3h1M119.5 86.2l.3 .3h5.1M120.7 92.8l-.6 .6v2.2M124.9 89h-2.2l-1.4 1.4h-5l-1.6 1.6v3.2l.4 .4M124.9 92h-1.6l-.7 .8 .4 .5v3.4l-1.8 1.8h-7.5l-4.9 5h-11l-3.2 3.3h18.4l7.5 7.5h3.3l.8-.8v-1.7l-.6-.7M124.9 87h-6.5l-.5 .4M124.9 88.5h-2.2l-1.5 1.5h-5.1l-2 2v3.6M124.9 90h-2.7l-.7 .7h-.8l-4.6 4.6v.3M124.9 81h-1l-.2 .2h-3.3l-.2 .2M124.9 81.5h-3.7l-.4 .5M124.9 90.5h-2.8l-.5 .6h-.8l-3.7 3.6v.9M126.6 88.9l1.1 1.1h.9"/>
<path d="M127.2 88.5h1.4M128.6 87h-1.2l-.5 .6M128.6 80.5h.9l2.5 2.6v8.6l.7 .7h12.2l2.3-2.3h12.4l1 .9v8l-.9 .9h-5.3l-.9-.9v-1.7M128.6 81h.9l2.2 2.2v8.6l.9 .9h12.5l2.3-2.2h5l1.1 1v.8M128.6 82.5h.9l1.2 1.3v8.4l1.5 1.5h13.1l1.7 1.7v3.6l.9 .9h4.1l.5-.5M128.6 82h.9l1.5 1.6v8.5l1.3 1.3h13.1l1.9 1.8v3.6l.7 .7h3.4l.8-.8v-2.8M128.6 81.5h.9l1.8 1.9v8.5l1.1 1.1M128.6 83h.9l.9 .9v8.4l1.6 1.7M128.6 92l-1.6 1.6v11.6l3.7 3.6h54.1l1.2 1.3h5.4l1.2 1.2v2.7l.4 .3h.8M132 94h.1M132.4 93h13.1l2 2h6.2l2.3 2.3M132.4 93h.1"/>
<path d="M156 92.3h-.8l-.5 .5M158.6 92.3l-1.2 .1M158.6 97.3l-1.2 .1M160 89.5l.9 .9v8.7l-1 1.1h-12.2l-1.1-1.1v-3.4l-1.6-1.7h-13M170.1 80.1v1.5l-.3 .4M185.8 83.2h-1.9l-1.2 1.2v2.4l-1.4 1.4M188.9 83.9l2.6 2.7h1.6v1l.4 .5h1.3l.2-.2h2.8l.3 .3M194.3 85l-.5 .5h-.7M194.5 93.7l-.3 .4v1.5M194.5 87.5h.1M194.5 87.5h6.4M195.4 80.5l.3 .3h4l.3-.3h.9"/>
<path d="M196.8 92.8l-.6 .6v2.2M199.2 91.1l-.2 .2h-2l-1.8 1.9v2.4M200.9 90.5h-2.7l-.5 .5h-1.3l-3.2 3.3v1.3M200.9 88.5h-2.1l-1.5 1.5h-5.1l-2 2v3.6M200.9 90h-2.7l-.7 .7h-1.2l-4.1 4.1v.8M200.9 81h-1l-.1 .2h-3.4l-.1 .1M200.9 81.5h-3.7l-.4 .4M200.9 92h-1.5l-.8 .8 .7 .6v3.2l-1.3 1.3h-9.8l-1.4 1.5v1.2l5 5M200.9 87l-6.6-.1-.6 .6M200.9 89h-2.1l-1.4 1.4h-5l-1.2 1.1v4.1M202.4 88.6v.6l.8 .8h1.4M203.2 88.5h1.4"/>
<path d="M204.6 81h.9l2.1 2.1v8.5l.8 .8h13.4l2.1-2.1h3.7l1.9 2M204.6 87h-1.3l-.4 .4M204.6 82.5h1l1 1.1v8.7l7.8 7.8h15.5l.3-.4M204.6 80.5h.9l2.4 2.4v8.6l.6 .6h13.2l2.1-2.1h11.3l.8 .8v8.2l-1 .9h-2.7l-2.7-2.6M204.6 81.5h1l1.7 1.7v8.8l7.4 7.4h8.3l.7-.7v-3.2l.2-.3h6.2l2 2.1M204.6 82h.9l1.5 1.4v8.8l7.5 7.5h10.6l.6-.6M204.6 83h1l.7 .7v8.7l8 8h21.8l.4-.4v-5.7M204.6 92v.7l-8.4 8.4M225.5 96.2l-1 1.1M232.1 92.3l-.8 .8h-.5M234.6 97.3l-.7 .7h-.5M234.6 92.3h-.5l-.8 .8"/>
<path d="M94.6 108.3h19.4l4.7 4.6v1.5M95.3 114.5h.1M95.4 114.5h5l.4-.4h13.8l.6 .7v8.4l2.6 2.6h.8M97.3 111.2l-1.5 1.5v.8l.7 .7h3.7l.5-.5h14l.9 .9v8.5l2.2 2.2h.8M97.4 113.7l.3-.4h1.8l.4 .4h.4l.3-.3h14.2l1.1 1.1v8.5l1.8 1.8h.9M100.1 113.1h14.9l1.2 1.3v8.4l1.5 1.5h.9M102.8 105.8l.7 .7h9.6l3 3h8.2l.2-.2h2.5l1 1.1v.3M116.6 112.7l-.1 5.5 1.2 1.1h.9M117.2 116.1l.2 .2h1.2M117.2 117.8h1.4M118.6 119.8h8.7l.3 .3M118.6 118.3h1.1l.3 .2v1.3"/>
<path d="M119 112.8h.1M119.7 105.1l.4-.3 .4 .3M119.9 105.1l.2-.2 .3 .2M119.9 105.1h.1M120.1 101.5v3.5M120.1 105l.2 .1M120.1 105l-.1 .1M120.2 104.8l-.4 .3M120.3 105.1h.1M122.3 118.3h-1.2l-.2 .2v1.3M122.3 118.8h6.2M122.9 112.6l-.9-.9h-.9l-1.1 1.1"/>
<path d="M127 104.5l-.5-.6h-3.4l-1.2 1.2h-14.4M127 110.7v2.2l-.6 .6M129 110.7v1.3l-.9 .9h-.3M129.5 118.8l-.6 .6-6.6-.1M130 110.7v.9l-3.6 3.7h-.8l-.6 .5h-2.7M130.1 119.7h1.6l2.6 2.7M131 110.7v.8l-4.1 4.1h-1.2l-.7 .7h-2.7M132 110.7v4.1l-1.2 1.1h-5l-1.3 1.4h-2.2M133 110.7v3.6l-2 2h-5.1l-1.5 1.5h-2.1M141.9 118.1v1.4l-3.6 3.7h-1.2M165.2 110.1h14.4l.9 .9M170.6 114.6h19.7l.2 .2v8.5l2.5 2.5h.8"/>
<path d="M172.5 111.2l-1.4 1.5v.9l.7 .7h18.6l.4 .4v8.5l2.2 2.1h.8M172.6 113.7l.2 .2h17.7l.6 .6v8.5l1.9 1.8h.8M175.3 113.1l.5 .5h14.9l.7 .8v8.4l1.6 1.5h.8M184.4 109.5l-.3-.4h-32.1l-5.6 5.7v.7M187.5 110.1l.3-.4 .4 .4M187.6 110.1l.2-.3 .3 .3M187.8 109.2h.1M187.8 109.2v.9M188.6 109.5l.2 .2 10.5 .1 .4-.4h2.5l1 1v.4M191.7 105.6v2.9M191.9 112.7v5.6l1 1h.9M192.4 117.8h1.4"/>
<path d="M192.7 110.4l.2 .2v.9l2.9 2.8h3.2l.8-.7M193.8 119.8h8.7l.4 .4M193.8 118.3h1.2l.2 .3v1.2M193.8 116.3l-1.2 .1M196.2 101.5v6.1l-1.4 1.4h-3.3l-.6-.5h-2.3l-.8 .7M196.2 101.8l1.9 2h3.4l.7 .7v.4M196.2 106.9h.1M197.5 118.3h-1.2l-.2 .3v1.2M197.5 118.8h6.2M198.1 112.6l-.9-.9h-.9l-1.1 1.1M202.2 110.8v2.2l-.6 .6M204.2 110.8v1.3l-.9 .9h-.3"/>
<path d="M204.7 118.9l-.5 .5-6.7-.1M205.2 110.8v.9l-3.6 3.6h-.8l-.5 .5h-2.8M205.3 119.8h1.6l2.6 2.6M206.2 110.8v.7l-4.1 4.2h-1.2l-.7 .6h-2.7M207.2 110.8v4l-1.1 1.2h-5l-1.4 1.3h-2.2M208.2 110.8v3.5l-2 2h-5.1l-1.5 1.5h-2.1M217.1 118.2v1.4l-3.3 3.4h-1.3M116.8 122.3v.6l.9 .9h.9M116.9 121.5l.4 .5v1l.4 .3h.9M122.3 120.3h4.8l.3 .4h.5l9.4 9.4v.4l.2 .2h.8M122.3 125.8h.9l.3-.3h4l.3 .3M122.5 120.7h1.1l9.7 9.7h1.3l.7-.7"/>
<path d="M126.4 124.4l-.4 .4h-3.7M126.9 125l-.1 .1h-3.4l-.1 .2h-1M128.8 120.7l1.3 .1M134 131.8l-1.6 1.7v.8M135.3 131.6l.6 .6h2.4M137.2 137l.1 2.4 .3 .3h.4M138.5 138.6h.1M138.5 138.6l.5 .6h2.3l.3-.3M139.6 134h-1l-.4 .4v1.5l.3 .4v2.3M139.7 135.3l1 1h1.8l.9 .9v1.2l-.6 .6M141.4 128.4h1.6M142.6 131.7l-.8 .1-1.1-1.1v-2.8l2-2h4.5l1.3 1.3v4.9l-.6 .6v.9h-1.7l-1.1 1.1h.7l1.7 1.7v2.5l-.8 .9h-.9l-.2-.2h-6.6l-.8-.8v-2.4l-1-1v-1.5"/>
<path d="M142.6 131.2h.7l.5 .6v.4l-1.1 1.2h-1.7l-.7 .7v1.1l-.1 .1h-.6M142.6 132.2h-.9l-1.4-1.4v-1.8l-.6-.6h-.1v2.5l-.4 .3h-1.7l-.7-.6h-1.9l-.2 .2h-.4l-2.5 2.5v1.8l2.7 2.8M142.6 130.7h4.1l.7 .7M143 128.4v1.4l-.4 .4M146.6 127.7h-1l-.7 .7h.3l2.8 2.8v.4l-.4 .4h-2.8l-2 2h-1M146.7 126.8h-2l-1.7 1.6M147.3 133l-.2-.2h-2l-2.5 2.5h-.8M151.3 132.9l-1.1 1.1v3l-3.2 3.1h-8.6l-.2 .2h-2.6l-6.8-6.7h-1.3M153.6 124.5l-1 1v1.2M156.8 126.8l-.8 .1M156.8 127.3l-.3 .4h-1.7v.8M157 124.3l-1.3-1.2h-2.7l-1.1 1.1v2.9l.4 .4"/>
<path d="M157.1 128.5h.4l1 1h.1M158.6 124.3v.4l-.9 .9v.6l-.2 .1h-.7M158.7 126.8h.7l.4 .4M192 122.6v.3l.9 .9h.9M192 121.8l.6 .5v.7l.3 .3h.9M197.5 120.3h4.8l10.4 10.5h.8M197.5 125.8h1l.2-.2h4l.3 .3M197.7 120.8h1.1l9.7 9.7h1.9M201.6 124.4l-.4 .4h-3.7M202.2 125l-.2 .2h-3.3l-.2 .1h-1M204 120.8h1.3M209.3 131.9l-1.7 1.7v.7"/>
<path d="M210.4 132.3h3.1M212.4 137l.1 2.4 .3 .2M213.5 131.8h.8l1.2 1.3v1.5l-.1 .1h-.6M214.8 134h-1.2l-.4 .4 .1 1.8 .3 .3v1.8l.9 .9h2.1l.4-.4M216.6 128.5h1.7M217 134.7h-.6l-.1 .1v1l.2 .2h3.3l2.2 2.2M217.8 132.3h-.8l-1.5-1.5v-1.8l-.6-.5h-.1v2.4l-.4 .4h-5.4l-2.3 2.3v1.3l3.1 3.1M217.8 131.3h.7l.5 .5v.5l-1.1 1.1h-1.3l-.8 .8v.7l-.4 .4h-.6l1.1 1.1h1.5l.2 .1v2.3l.3 .3h3.3M217.8 131.8l-.8 .1-1.1-1.1v-2.8l2-2.1h4.5l1.3 1.3v5l-.6 .6v.8h-1.7l-1.1 1.1h.7l1.7 1.7v2.6l-.6 .6-1.2 .1-.1-.2h-6.5l-1-1v-1.9l-.8-.7-.1-1.9M217.8 130.8h4.2l.6 .7M218.3 128.5v1.3l-.5 .5M221.8 127.7h-1l-.7 .8h.4l2.7 2.8v.4l-.3 .3h-2.9l-2 2h-1"/>
<path d="M221.9 126.8h-2l-1.6 1.7M222.5 133l-.1-.1h-2.1l-2.4 2.4h-.9M229.5 125.1l-1.2 1.2M230.9 126.7l.2 .2h.9M232 127.4l-.3 .3-.6 .1h-.9l-.1-.1M232.2 124.4h-1.1l-1.1-1.1h-1l-1.5 1.4v2.8M233 128.4v.4l.8 .7M233.8 124.3l-.5 .6v.8l-.6 .6h-.7M233.9 126.9h.8l.3 .3M145.7 140.1h.1"/>
</g>
<path d="M91.3 71.1l1.9 1.9v6.2l-.6 .7h-.3l-.8 .7h-1.1M96.1 71.4l-3.7-3.7h-3.9l-.9 .9v5.5l1 .9-1 1v2l.9 .9M167.3 71l2 2v6.2l-.6 .6h-.7l-.8 .8h-.8M172 70.8h-.4l-3.2-3.1h-3.9l-.8 .8v5.5l.9 .9-1 1v2.1l.9 .9" fill="none" stroke="#000" stroke-width=".3"/>
<path d="M156.8 125.7h-.8l-.8 .8h-.7l-.6 .6v6.2l2 2M158.7 127.4l.9 .9v2.1l-1 1 .9 .9v5.5l-.8 .8h-3.9l-3.7-3.7M232 125.7h-1.3l-.8 .8h-.5l-.3 .3v6.6l2 1.9M233.9 127.5l.9 .9v2l-1 1 .9 .9v5.5l-.8 .9h-3.9l-3.7-3.7" fill="none" stroke="#000" stroke-width=".5"/>
<path d="M143.6 75.5h4.1l3.9 3.9M157.1 79.4l2.4 2.4v5.6l-1.3 1.3h-14.6M219.7 75.5h4l4 3.9M233.2 79.4l2.3 2.4v5.6l-1.3 1.3h-14.5M103.6 117.6h-14.6l-1.3 1.3v5.6l1.4 1.4h.9M178.8 117.7h-14.6l-1.3 1.3v5.6M162.9 124.6l2.4 2.3M170.8 126.9l3.9 4h4.1" fill="none" stroke="#000" stroke-width="2"/>
<g fill="none" stroke="#000" stroke-width=".25">
<path d="M95.9 76v2.3l2.9 2.9h5.5l3.3-3.3M106.6 67.7l.8 .8v.2M172 75.9v2.3l2.8 2.9h5.6l3.2-3.2M183.7 67.5l-.2 .2v1M121.8 82.1h.1M124.9 82l-3.1 .1M149.7 95.9l-1.3 1.4M197.9 82.1h.1M200.9 82l-3 .1M91.4 111.5l.5 .5v3.2l.7 .6h7.1l.6-.5M166.6 111.5l.5 .5v3.2l.7 .7h7.2l.5-.5M125.3 124.2l-3 .1"/>
<path d="M139.6 128.4l3.3-3.2h5.5l2.9 2.9v2.3M139.7 137.6v.2l.8 .8M200.6 124.3h-3.1M200.6 124.3h.1M202.5 132.1v.6l7.5 7.5h12.8l1.5-1.4v-3.6l2.2-2.2M214.8 128.5l3.3-3.3h5.5l2.9 2.9v2.3M215 137.7v.2l.7 .8"/>
</g>
</svg>
